# Generated deterministically by seda-macro-lef-normalizer-v1; recipe orfs-asap7-fakeram-m4-v1.
VERSION 5.8 ;
BUSBITCHARS "[]" ;
DIVIDERCHAR "/" ;

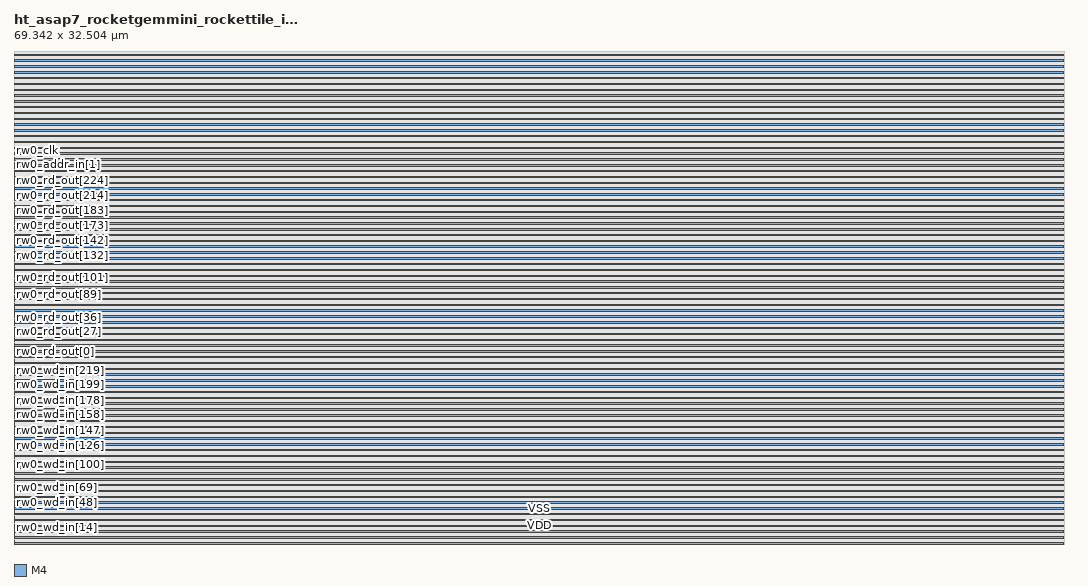
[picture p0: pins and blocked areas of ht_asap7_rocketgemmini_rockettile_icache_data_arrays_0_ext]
MACRO ht_asap7_rocketgemmini_rockettile_icache_data_arrays_0_ext
  FOREIGN ht_asap7_rocketgemmini_rockettile_icache_data_arrays_0_ext 0 0 ;
  CLASS BLOCK ;
  ORIGIN 0 0 ;
  SIZE 69.342 BY 32.504 ;
  SYMMETRY X Y R90 ;
  PIN rw0_wmask_in[0]
    DIRECTION INPUT ;
    USE SIGNAL ;
    SHAPE ABUTMENT ;
    PORT
      LAYER M4 ;
      RECT 0 0.048 0.024 0.072 ;
    END
  END rw0_wmask_in[0]
  PIN rw0_wmask_in[1]
    DIRECTION INPUT ;
    USE SIGNAL ;
    SHAPE ABUTMENT ;
    PORT
      LAYER M4 ;
      RECT 0 0.096 0.024 0.12 ;
    END
  END rw0_wmask_in[1]
  PIN rw0_wmask_in[2]
    DIRECTION INPUT ;
    USE SIGNAL ;
    SHAPE ABUTMENT ;
    PORT
      LAYER M4 ;
      RECT 0 0.144 0.024 0.168 ;
    END
  END rw0_wmask_in[2]
  PIN rw0_wmask_in[3]
    DIRECTION INPUT ;
    USE SIGNAL ;
    SHAPE ABUTMENT ;
    PORT
      LAYER M4 ;
      RECT 0 0.192 0.024 0.216 ;
    END
  END rw0_wmask_in[3]
  PIN rw0_wmask_in[4]
    DIRECTION INPUT ;
    USE SIGNAL ;
    SHAPE ABUTMENT ;
    PORT
      LAYER M4 ;
      RECT 0 0.24 0.024 0.264 ;
    END
  END rw0_wmask_in[4]
  PIN rw0_wmask_in[5]
    DIRECTION INPUT ;
    USE SIGNAL ;
    SHAPE ABUTMENT ;
    PORT
      LAYER M4 ;
      RECT 0 0.288 0.024 0.312 ;
    END
  END rw0_wmask_in[5]
  PIN rw0_wmask_in[6]
    DIRECTION INPUT ;
    USE SIGNAL ;
    SHAPE ABUTMENT ;
    PORT
      LAYER M4 ;
      RECT 0 0.336 0.024 0.36 ;
    END
  END rw0_wmask_in[6]
  PIN rw0_wmask_in[7]
    DIRECTION INPUT ;
    USE SIGNAL ;
    SHAPE ABUTMENT ;
    PORT
      LAYER M4 ;
      RECT 0 0.384 0.024 0.408 ;
    END
  END rw0_wmask_in[7]
  PIN rw0_wd_in[0]
    DIRECTION INPUT ;
    USE SIGNAL ;
    SHAPE ABUTMENT ;
    PORT
      LAYER M4 ;
      RECT 0 0.432 0.024 0.456 ;
    END
  END rw0_wd_in[0]
  PIN rw0_wd_in[1]
    DIRECTION INPUT ;
    USE SIGNAL ;
    SHAPE ABUTMENT ;
    PORT
      LAYER M4 ;
      RECT 0 0.48 0.024 0.504 ;
    END
  END rw0_wd_in[1]
  PIN rw0_wd_in[2]
    DIRECTION INPUT ;
    USE SIGNAL ;
    SHAPE ABUTMENT ;
    PORT
      LAYER M4 ;
      RECT 0 0.528 0.024 0.552 ;
    END
  END rw0_wd_in[2]
  PIN rw0_wd_in[3]
    DIRECTION INPUT ;
    USE SIGNAL ;
    SHAPE ABUTMENT ;
    PORT
      LAYER M4 ;
      RECT 0 0.576 0.024 0.6 ;
    END
  END rw0_wd_in[3]
  PIN rw0_wd_in[4]
    DIRECTION INPUT ;
    USE SIGNAL ;
    SHAPE ABUTMENT ;
    PORT
      LAYER M4 ;
      RECT 0 0.624 0.024 0.648 ;
    END
  END rw0_wd_in[4]
  PIN rw0_wd_in[5]
    DIRECTION INPUT ;
    USE SIGNAL ;
    SHAPE ABUTMENT ;
    PORT
      LAYER M4 ;
      RECT 0 0.672 0.024 0.696 ;
    END
  END rw0_wd_in[5]
  PIN rw0_wd_in[6]
    DIRECTION INPUT ;
    USE SIGNAL ;
    SHAPE ABUTMENT ;
    PORT
      LAYER M4 ;
      RECT 0 0.72 0.024 0.744 ;
    END
  END rw0_wd_in[6]
  PIN rw0_wd_in[7]
    DIRECTION INPUT ;
    USE SIGNAL ;
    SHAPE ABUTMENT ;
    PORT
      LAYER M4 ;
      RECT 0 0.768 0.024 0.792 ;
    END
  END rw0_wd_in[7]
  PIN rw0_wd_in[8]
    DIRECTION INPUT ;
    USE SIGNAL ;
    SHAPE ABUTMENT ;
    PORT
      LAYER M4 ;
      RECT 0 0.816 0.024 0.84 ;
    END
  END rw0_wd_in[8]
  PIN rw0_wd_in[9]
    DIRECTION INPUT ;
    USE SIGNAL ;
    SHAPE ABUTMENT ;
    PORT
      LAYER M4 ;
      RECT 0 0.864 0.024 0.888 ;
    END
  END rw0_wd_in[9]
  PIN rw0_wd_in[10]
    DIRECTION INPUT ;
    USE SIGNAL ;
    SHAPE ABUTMENT ;
    PORT
      LAYER M4 ;
      RECT 0 0.912 0.024 0.936 ;
    END
  END rw0_wd_in[10]
  PIN rw0_wd_in[11]
    DIRECTION INPUT ;
    USE SIGNAL ;
    SHAPE ABUTMENT ;
    PORT
      LAYER M4 ;
      RECT 0 0.96 0.024 0.984 ;
    END
  END rw0_wd_in[11]
  PIN rw0_wd_in[12]
    DIRECTION INPUT ;
    USE SIGNAL ;
    SHAPE ABUTMENT ;
    PORT
      LAYER M4 ;
      RECT 0 1.008 0.024 1.032 ;
    END
  END rw0_wd_in[12]
  PIN rw0_wd_in[13]
    DIRECTION INPUT ;
    USE SIGNAL ;
    SHAPE ABUTMENT ;
    PORT
      LAYER M4 ;
      RECT 0 1.056 0.024 1.08 ;
    END
  END rw0_wd_in[13]
  PIN rw0_wd_in[14]
    DIRECTION INPUT ;
    USE SIGNAL ;
    SHAPE ABUTMENT ;
    PORT
      LAYER M4 ;
      RECT 0 1.104 0.024 1.128 ;
    END
  END rw0_wd_in[14]
  PIN rw0_wd_in[15]
    DIRECTION INPUT ;
    USE SIGNAL ;
    SHAPE ABUTMENT ;
    PORT
      LAYER M4 ;
      RECT 0 1.152 0.024 1.176 ;
    END
  END rw0_wd_in[15]
  PIN rw0_wd_in[16]
    DIRECTION INPUT ;
    USE SIGNAL ;
    SHAPE ABUTMENT ;
    PORT
      LAYER M4 ;
      RECT 0 1.2 0.024 1.224 ;
    END
  END rw0_wd_in[16]
  PIN rw0_wd_in[17]
    DIRECTION INPUT ;
    USE SIGNAL ;
    SHAPE ABUTMENT ;
    PORT
      LAYER M4 ;
      RECT 0 1.248 0.024 1.272 ;
    END
  END rw0_wd_in[17]
  PIN rw0_wd_in[18]
    DIRECTION INPUT ;
    USE SIGNAL ;
    SHAPE ABUTMENT ;
    PORT
      LAYER M4 ;
      RECT 0 1.296 0.024 1.32 ;
    END
  END rw0_wd_in[18]
  PIN rw0_wd_in[19]
    DIRECTION INPUT ;
    USE SIGNAL ;
    SHAPE ABUTMENT ;
    PORT
      LAYER M4 ;
      RECT 0 1.344 0.024 1.368 ;
    END
  END rw0_wd_in[19]
  PIN rw0_wd_in[20]
    DIRECTION INPUT ;
    USE SIGNAL ;
    SHAPE ABUTMENT ;
    PORT
      LAYER M4 ;
      RECT 0 1.392 0.024 1.416 ;
    END
  END rw0_wd_in[20]
  PIN rw0_wd_in[21]
    DIRECTION INPUT ;
    USE SIGNAL ;
    SHAPE ABUTMENT ;
    PORT
      LAYER M4 ;
      RECT 0 1.44 0.024 1.464 ;
    END
  END rw0_wd_in[21]
  PIN rw0_wd_in[22]
    DIRECTION INPUT ;
    USE SIGNAL ;
    SHAPE ABUTMENT ;
    PORT
      LAYER M4 ;
      RECT 0 1.488 0.024 1.512 ;
    END
  END rw0_wd_in[22]
  PIN rw0_wd_in[23]
    DIRECTION INPUT ;
    USE SIGNAL ;
    SHAPE ABUTMENT ;
    PORT
      LAYER M4 ;
      RECT 0 1.536 0.024 1.56 ;
    END
  END rw0_wd_in[23]
  PIN rw0_wd_in[24]
    DIRECTION INPUT ;
    USE SIGNAL ;
    SHAPE ABUTMENT ;
    PORT
      LAYER M4 ;
      RECT 0 1.584 0.024 1.608 ;
    END
  END rw0_wd_in[24]
  PIN rw0_wd_in[25]
    DIRECTION INPUT ;
    USE SIGNAL ;
    SHAPE ABUTMENT ;
    PORT
      LAYER M4 ;
      RECT 0 1.632 0.024 1.656 ;
    END
  END rw0_wd_in[25]
  PIN rw0_wd_in[26]
    DIRECTION INPUT ;
    USE SIGNAL ;
    SHAPE ABUTMENT ;
    PORT
      LAYER M4 ;
      RECT 0 1.68 0.024 1.704 ;
    END
  END rw0_wd_in[26]
  PIN rw0_wd_in[27]
    DIRECTION INPUT ;
    USE SIGNAL ;
    SHAPE ABUTMENT ;
    PORT
      LAYER M4 ;
      RECT 0 1.728 0.024 1.752 ;
    END
  END rw0_wd_in[27]
  PIN rw0_wd_in[28]
    DIRECTION INPUT ;
    USE SIGNAL ;
    SHAPE ABUTMENT ;
    PORT
      LAYER M4 ;
      RECT 0 1.776 0.024 1.8 ;
    END
  END rw0_wd_in[28]
  PIN rw0_wd_in[29]
    DIRECTION INPUT ;
    USE SIGNAL ;
    SHAPE ABUTMENT ;
    PORT
      LAYER M4 ;
      RECT 0 1.824 0.024 1.848 ;
    END
  END rw0_wd_in[29]
  PIN rw0_wd_in[30]
    DIRECTION INPUT ;
    USE SIGNAL ;
    SHAPE ABUTMENT ;
    PORT
      LAYER M4 ;
      RECT 0 1.872 0.024 1.896 ;
    END
  END rw0_wd_in[30]
  PIN rw0_wd_in[31]
    DIRECTION INPUT ;
    USE SIGNAL ;
    SHAPE ABUTMENT ;
    PORT
      LAYER M4 ;
      RECT 0 1.92 0.024 1.944 ;
    END
  END rw0_wd_in[31]
  PIN rw0_wd_in[32]
    DIRECTION INPUT ;
    USE SIGNAL ;
    SHAPE ABUTMENT ;
    PORT
      LAYER M4 ;
      RECT 0 1.968 0.024 1.992 ;
    END
  END rw0_wd_in[32]
  PIN rw0_wd_in[33]
    DIRECTION INPUT ;
    USE SIGNAL ;
    SHAPE ABUTMENT ;
    PORT
      LAYER M4 ;
      RECT 0 2.016 0.024 2.04 ;
    END
  END rw0_wd_in[33]
  PIN rw0_wd_in[34]
    DIRECTION INPUT ;
    USE SIGNAL ;
    SHAPE ABUTMENT ;
    PORT
      LAYER M4 ;
      RECT 0 2.064 0.024 2.088 ;
    END
  END rw0_wd_in[34]
  PIN rw0_wd_in[35]
    DIRECTION INPUT ;
    USE SIGNAL ;
    SHAPE ABUTMENT ;
    PORT
      LAYER M4 ;
      RECT 0 2.112 0.024 2.136 ;
    END
  END rw0_wd_in[35]
  PIN rw0_wd_in[36]
    DIRECTION INPUT ;
    USE SIGNAL ;
    SHAPE ABUTMENT ;
    PORT
      LAYER M4 ;
      RECT 0 2.16 0.024 2.184 ;
    END
  END rw0_wd_in[36]
  PIN rw0_wd_in[37]
    DIRECTION INPUT ;
    USE SIGNAL ;
    SHAPE ABUTMENT ;
    PORT
      LAYER M4 ;
      RECT 0 2.208 0.024 2.232 ;
    END
  END rw0_wd_in[37]
  PIN rw0_wd_in[38]
    DIRECTION INPUT ;
    USE SIGNAL ;
    SHAPE ABUTMENT ;
    PORT
      LAYER M4 ;
      RECT 0 2.256 0.024 2.28 ;
    END
  END rw0_wd_in[38]
  PIN rw0_wd_in[39]
    DIRECTION INPUT ;
    USE SIGNAL ;
    SHAPE ABUTMENT ;
    PORT
      LAYER M4 ;
      RECT 0 2.304 0.024 2.328 ;
    END
  END rw0_wd_in[39]
  PIN rw0_wd_in[40]
    DIRECTION INPUT ;
    USE SIGNAL ;
    SHAPE ABUTMENT ;
    PORT
      LAYER M4 ;
      RECT 0 2.352 0.024 2.376 ;
    END
  END rw0_wd_in[40]
  PIN rw0_wd_in[41]
    DIRECTION INPUT ;
    USE SIGNAL ;
    SHAPE ABUTMENT ;
    PORT
      LAYER M4 ;
      RECT 0 2.4 0.024 2.424 ;
    END
  END rw0_wd_in[41]
  PIN rw0_wd_in[42]
    DIRECTION INPUT ;
    USE SIGNAL ;
    SHAPE ABUTMENT ;
    PORT
      LAYER M4 ;
      RECT 0 2.448 0.024 2.472 ;
    END
  END rw0_wd_in[42]
  PIN rw0_wd_in[43]
    DIRECTION INPUT ;
    USE SIGNAL ;
    SHAPE ABUTMENT ;
    PORT
      LAYER M4 ;
      RECT 0 2.496 0.024 2.52 ;
    END
  END rw0_wd_in[43]
  PIN rw0_wd_in[44]
    DIRECTION INPUT ;
    USE SIGNAL ;
    SHAPE ABUTMENT ;
    PORT
      LAYER M4 ;
      RECT 0 2.544 0.024 2.568 ;
    END
  END rw0_wd_in[44]
  PIN rw0_wd_in[45]
    DIRECTION INPUT ;
    USE SIGNAL ;
    SHAPE ABUTMENT ;
    PORT
      LAYER M4 ;
      RECT 0 2.592 0.024 2.616 ;
    END
  END rw0_wd_in[45]
  PIN rw0_wd_in[46]
    DIRECTION INPUT ;
    USE SIGNAL ;
    SHAPE ABUTMENT ;
    PORT
      LAYER M4 ;
      RECT 0 2.64 0.024 2.664 ;
    END
  END rw0_wd_in[46]
  PIN rw0_wd_in[47]
    DIRECTION INPUT ;
    USE SIGNAL ;
    SHAPE ABUTMENT ;
    PORT
      LAYER M4 ;
      RECT 0 2.688 0.024 2.712 ;
    END
  END rw0_wd_in[47]
  PIN rw0_wd_in[48]
    DIRECTION INPUT ;
    USE SIGNAL ;
    SHAPE ABUTMENT ;
    PORT
      LAYER M4 ;
      RECT 0 2.736 0.024 2.76 ;
    END
  END rw0_wd_in[48]
  PIN rw0_wd_in[49]
    DIRECTION INPUT ;
    USE SIGNAL ;
    SHAPE ABUTMENT ;
    PORT
      LAYER M4 ;
      RECT 0 2.784 0.024 2.808 ;
    END
  END rw0_wd_in[49]
  PIN rw0_wd_in[50]
    DIRECTION INPUT ;
    USE SIGNAL ;
    SHAPE ABUTMENT ;
    PORT
      LAYER M4 ;
      RECT 0 2.832 0.024 2.856 ;
    END
  END rw0_wd_in[50]
  PIN rw0_wd_in[51]
    DIRECTION INPUT ;
    USE SIGNAL ;
    SHAPE ABUTMENT ;
    PORT
      LAYER M4 ;
      RECT 0 2.88 0.024 2.904 ;
    END
  END rw0_wd_in[51]
  PIN rw0_wd_in[52]
    DIRECTION INPUT ;
    USE SIGNAL ;
    SHAPE ABUTMENT ;
    PORT
      LAYER M4 ;
      RECT 0 2.928 0.024 2.952 ;
    END
  END rw0_wd_in[52]
  PIN rw0_wd_in[53]
    DIRECTION INPUT ;
    USE SIGNAL ;
    SHAPE ABUTMENT ;
    PORT
      LAYER M4 ;
      RECT 0 2.976 0.024 3 ;
    END
  END rw0_wd_in[53]
  PIN rw0_wd_in[54]
    DIRECTION INPUT ;
    USE SIGNAL ;
    SHAPE ABUTMENT ;
    PORT
      LAYER M4 ;
      RECT 0 3.024 0.024 3.048 ;
    END
  END rw0_wd_in[54]
  PIN rw0_wd_in[55]
    DIRECTION INPUT ;
    USE SIGNAL ;
    SHAPE ABUTMENT ;
    PORT
      LAYER M4 ;
      RECT 0 3.072 0.024 3.096 ;
    END
  END rw0_wd_in[55]
  PIN rw0_wd_in[56]
    DIRECTION INPUT ;
    USE SIGNAL ;
    SHAPE ABUTMENT ;
    PORT
      LAYER M4 ;
      RECT 0 3.12 0.024 3.144 ;
    END
  END rw0_wd_in[56]
  PIN rw0_wd_in[57]
    DIRECTION INPUT ;
    USE SIGNAL ;
    SHAPE ABUTMENT ;
    PORT
      LAYER M4 ;
      RECT 0 3.168 0.024 3.192 ;
    END
  END rw0_wd_in[57]
  PIN rw0_wd_in[58]
    DIRECTION INPUT ;
    USE SIGNAL ;
    SHAPE ABUTMENT ;
    PORT
      LAYER M4 ;
      RECT 0 3.216 0.024 3.24 ;
    END
  END rw0_wd_in[58]
  PIN rw0_wd_in[59]
    DIRECTION INPUT ;
    USE SIGNAL ;
    SHAPE ABUTMENT ;
    PORT
      LAYER M4 ;
      RECT 0 3.264 0.024 3.288 ;
    END
  END rw0_wd_in[59]
  PIN rw0_wd_in[60]
    DIRECTION INPUT ;
    USE SIGNAL ;
    SHAPE ABUTMENT ;
    PORT
      LAYER M4 ;
      RECT 0 3.312 0.024 3.336 ;
    END
  END rw0_wd_in[60]
  PIN rw0_wd_in[61]
    DIRECTION INPUT ;
    USE SIGNAL ;
    SHAPE ABUTMENT ;
    PORT
      LAYER M4 ;
      RECT 0 3.36 0.024 3.384 ;
    END
  END rw0_wd_in[61]
  PIN rw0_wd_in[62]
    DIRECTION INPUT ;
    USE SIGNAL ;
    SHAPE ABUTMENT ;
    PORT
      LAYER M4 ;
      RECT 0 3.408 0.024 3.432 ;
    END
  END rw0_wd_in[62]
  PIN rw0_wd_in[63]
    DIRECTION INPUT ;
    USE SIGNAL ;
    SHAPE ABUTMENT ;
    PORT
      LAYER M4 ;
      RECT 0 3.456 0.024 3.48 ;
    END
  END rw0_wd_in[63]
  PIN rw0_wd_in[64]
    DIRECTION INPUT ;
    USE SIGNAL ;
    SHAPE ABUTMENT ;
    PORT
      LAYER M4 ;
      RECT 0 3.504 0.024 3.528 ;
    END
  END rw0_wd_in[64]
  PIN rw0_wd_in[65]
    DIRECTION INPUT ;
    USE SIGNAL ;
    SHAPE ABUTMENT ;
    PORT
      LAYER M4 ;
      RECT 0 3.552 0.024 3.576 ;
    END
  END rw0_wd_in[65]
  PIN rw0_wd_in[66]
    DIRECTION INPUT ;
    USE SIGNAL ;
    SHAPE ABUTMENT ;
    PORT
      LAYER M4 ;
      RECT 0 3.6 0.024 3.624 ;
    END
  END rw0_wd_in[66]
  PIN rw0_wd_in[67]
    DIRECTION INPUT ;
    USE SIGNAL ;
    SHAPE ABUTMENT ;
    PORT
      LAYER M4 ;
      RECT 0 3.648 0.024 3.672 ;
    END
  END rw0_wd_in[67]
  PIN rw0_wd_in[68]
    DIRECTION INPUT ;
    USE SIGNAL ;
    SHAPE ABUTMENT ;
    PORT
      LAYER M4 ;
      RECT 0 3.696 0.024 3.72 ;
    END
  END rw0_wd_in[68]
  PIN rw0_wd_in[69]
    DIRECTION INPUT ;
    USE SIGNAL ;
    SHAPE ABUTMENT ;
    PORT
      LAYER M4 ;
      RECT 0 3.744 0.024 3.768 ;
    END
  END rw0_wd_in[69]
  PIN rw0_wd_in[70]
    DIRECTION INPUT ;
    USE SIGNAL ;
    SHAPE ABUTMENT ;
    PORT
      LAYER M4 ;
      RECT 0 3.792 0.024 3.816 ;
    END
  END rw0_wd_in[70]
  PIN rw0_wd_in[71]
    DIRECTION INPUT ;
    USE SIGNAL ;
    SHAPE ABUTMENT ;
    PORT
      LAYER M4 ;
      RECT 0 3.84 0.024 3.864 ;
    END
  END rw0_wd_in[71]
  PIN rw0_wd_in[72]
    DIRECTION INPUT ;
    USE SIGNAL ;
    SHAPE ABUTMENT ;
    PORT
      LAYER M4 ;
      RECT 0 3.888 0.024 3.912 ;
    END
  END rw0_wd_in[72]
  PIN rw0_wd_in[73]
    DIRECTION INPUT ;
    USE SIGNAL ;
    SHAPE ABUTMENT ;
    PORT
      LAYER M4 ;
      RECT 0 3.936 0.024 3.96 ;
    END
  END rw0_wd_in[73]
  PIN rw0_wd_in[74]
    DIRECTION INPUT ;
    USE SIGNAL ;
    SHAPE ABUTMENT ;
    PORT
      LAYER M4 ;
      RECT 0 3.984 0.024 4.008 ;
    END
  END rw0_wd_in[74]
  PIN rw0_wd_in[75]
    DIRECTION INPUT ;
    USE SIGNAL ;
    SHAPE ABUTMENT ;
    PORT
      LAYER M4 ;
      RECT 0 4.032 0.024 4.056 ;
    END
  END rw0_wd_in[75]
  PIN rw0_wd_in[76]
    DIRECTION INPUT ;
    USE SIGNAL ;
    SHAPE ABUTMENT ;
    PORT
      LAYER M4 ;
      RECT 0 4.08 0.024 4.104 ;
    END
  END rw0_wd_in[76]
  PIN rw0_wd_in[77]
    DIRECTION INPUT ;
    USE SIGNAL ;
    SHAPE ABUTMENT ;
    PORT
      LAYER M4 ;
      RECT 0 4.128 0.024 4.152 ;
    END
  END rw0_wd_in[77]
  PIN rw0_wd_in[78]
    DIRECTION INPUT ;
    USE SIGNAL ;
    SHAPE ABUTMENT ;
    PORT
      LAYER M4 ;
      RECT 0 4.176 0.024 4.2 ;
    END
  END rw0_wd_in[78]
  PIN rw0_wd_in[79]
    DIRECTION INPUT ;
    USE SIGNAL ;
    SHAPE ABUTMENT ;
    PORT
      LAYER M4 ;
      RECT 0 4.224 0.024 4.248 ;
    END
  END rw0_wd_in[79]
  PIN rw0_wd_in[80]
    DIRECTION INPUT ;
    USE SIGNAL ;
    SHAPE ABUTMENT ;
    PORT
      LAYER M4 ;
      RECT 0 4.272 0.024 4.296 ;
    END
  END rw0_wd_in[80]
  PIN rw0_wd_in[81]
    DIRECTION INPUT ;
    USE SIGNAL ;
    SHAPE ABUTMENT ;
    PORT
      LAYER M4 ;
      RECT 0 4.32 0.024 4.344 ;
    END
  END rw0_wd_in[81]
  PIN rw0_wd_in[82]
    DIRECTION INPUT ;
    USE SIGNAL ;
    SHAPE ABUTMENT ;
    PORT
      LAYER M4 ;
      RECT 0 4.368 0.024 4.392 ;
    END
  END rw0_wd_in[82]
  PIN rw0_wd_in[83]
    DIRECTION INPUT ;
    USE SIGNAL ;
    SHAPE ABUTMENT ;
    PORT
      LAYER M4 ;
      RECT 0 4.416 0.024 4.44 ;
    END
  END rw0_wd_in[83]
  PIN rw0_wd_in[84]
    DIRECTION INPUT ;
    USE SIGNAL ;
    SHAPE ABUTMENT ;
    PORT
      LAYER M4 ;
      RECT 0 4.464 0.024 4.488 ;
    END
  END rw0_wd_in[84]
  PIN rw0_wd_in[85]
    DIRECTION INPUT ;
    USE SIGNAL ;
    SHAPE ABUTMENT ;
    PORT
      LAYER M4 ;
      RECT 0 4.512 0.024 4.536 ;
    END
  END rw0_wd_in[85]
  PIN rw0_wd_in[86]
    DIRECTION INPUT ;
    USE SIGNAL ;
    SHAPE ABUTMENT ;
    PORT
      LAYER M4 ;
      RECT 0 4.56 0.024 4.584 ;
    END
  END rw0_wd_in[86]
  PIN rw0_wd_in[87]
    DIRECTION INPUT ;
    USE SIGNAL ;
    SHAPE ABUTMENT ;
    PORT
      LAYER M4 ;
      RECT 0 4.608 0.024 4.632 ;
    END
  END rw0_wd_in[87]
  PIN rw0_wd_in[88]
    DIRECTION INPUT ;
    USE SIGNAL ;
    SHAPE ABUTMENT ;
    PORT
      LAYER M4 ;
      RECT 0 4.656 0.024 4.68 ;
    END
  END rw0_wd_in[88]
  PIN rw0_wd_in[89]
    DIRECTION INPUT ;
    USE SIGNAL ;
    SHAPE ABUTMENT ;
    PORT
      LAYER M4 ;
      RECT 0 4.704 0.024 4.728 ;
    END
  END rw0_wd_in[89]
  PIN rw0_wd_in[90]
    DIRECTION INPUT ;
    USE SIGNAL ;
    SHAPE ABUTMENT ;
    PORT
      LAYER M4 ;
      RECT 0 4.752 0.024 4.776 ;
    END
  END rw0_wd_in[90]
  PIN rw0_wd_in[91]
    DIRECTION INPUT ;
    USE SIGNAL ;
    SHAPE ABUTMENT ;
    PORT
      LAYER M4 ;
      RECT 0 4.8 0.024 4.824 ;
    END
  END rw0_wd_in[91]
  PIN rw0_wd_in[92]
    DIRECTION INPUT ;
    USE SIGNAL ;
    SHAPE ABUTMENT ;
    PORT
      LAYER M4 ;
      RECT 0 4.848 0.024 4.872 ;
    END
  END rw0_wd_in[92]
  PIN rw0_wd_in[93]
    DIRECTION INPUT ;
    USE SIGNAL ;
    SHAPE ABUTMENT ;
    PORT
      LAYER M4 ;
      RECT 0 4.896 0.024 4.92 ;
    END
  END rw0_wd_in[93]
  PIN rw0_wd_in[94]
    DIRECTION INPUT ;
    USE SIGNAL ;
    SHAPE ABUTMENT ;
    PORT
      LAYER M4 ;
      RECT 0 4.944 0.024 4.968 ;
    END
  END rw0_wd_in[94]
  PIN rw0_wd_in[95]
    DIRECTION INPUT ;
    USE SIGNAL ;
    SHAPE ABUTMENT ;
    PORT
      LAYER M4 ;
      RECT 0 4.992 0.024 5.016 ;
    END
  END rw0_wd_in[95]
  PIN rw0_wd_in[96]
    DIRECTION INPUT ;
    USE SIGNAL ;
    SHAPE ABUTMENT ;
    PORT
      LAYER M4 ;
      RECT 0 5.04 0.024 5.064 ;
    END
  END rw0_wd_in[96]
  PIN rw0_wd_in[97]
    DIRECTION INPUT ;
    USE SIGNAL ;
    SHAPE ABUTMENT ;
    PORT
      LAYER M4 ;
      RECT 0 5.088 0.024 5.112 ;
    END
  END rw0_wd_in[97]
  PIN rw0_wd_in[98]
    DIRECTION INPUT ;
    USE SIGNAL ;
    SHAPE ABUTMENT ;
    PORT
      LAYER M4 ;
      RECT 0 5.136 0.024 5.16 ;
    END
  END rw0_wd_in[98]
  PIN rw0_wd_in[99]
    DIRECTION INPUT ;
    USE SIGNAL ;
    SHAPE ABUTMENT ;
    PORT
      LAYER M4 ;
      RECT 0 5.184 0.024 5.208 ;
    END
  END rw0_wd_in[99]
  PIN rw0_wd_in[100]
    DIRECTION INPUT ;
    USE SIGNAL ;
    SHAPE ABUTMENT ;
    PORT
      LAYER M4 ;
      RECT 0 5.232 0.024 5.256 ;
    END
  END rw0_wd_in[100]
  PIN rw0_wd_in[101]
    DIRECTION INPUT ;
    USE SIGNAL ;
    SHAPE ABUTMENT ;
    PORT
      LAYER M4 ;
      RECT 0 5.28 0.024 5.304 ;
    END
  END rw0_wd_in[101]
  PIN rw0_wd_in[102]
    DIRECTION INPUT ;
    USE SIGNAL ;
    SHAPE ABUTMENT ;
    PORT
      LAYER M4 ;
      RECT 0 5.328 0.024 5.352 ;
    END
  END rw0_wd_in[102]
  PIN rw0_wd_in[103]
    DIRECTION INPUT ;
    USE SIGNAL ;
    SHAPE ABUTMENT ;
    PORT
      LAYER M4 ;
      RECT 0 5.376 0.024 5.4 ;
    END
  END rw0_wd_in[103]
  PIN rw0_wd_in[104]
    DIRECTION INPUT ;
    USE SIGNAL ;
    SHAPE ABUTMENT ;
    PORT
      LAYER M4 ;
      RECT 0 5.424 0.024 5.448 ;
    END
  END rw0_wd_in[104]
  PIN rw0_wd_in[105]
    DIRECTION INPUT ;
    USE SIGNAL ;
    SHAPE ABUTMENT ;
    PORT
      LAYER M4 ;
      RECT 0 5.472 0.024 5.496 ;
    END
  END rw0_wd_in[105]
  PIN rw0_wd_in[106]
    DIRECTION INPUT ;
    USE SIGNAL ;
    SHAPE ABUTMENT ;
    PORT
      LAYER M4 ;
      RECT 0 5.52 0.024 5.544 ;
    END
  END rw0_wd_in[106]
  PIN rw0_wd_in[107]
    DIRECTION INPUT ;
    USE SIGNAL ;
    SHAPE ABUTMENT ;
    PORT
      LAYER M4 ;
      RECT 0 5.568 0.024 5.592 ;
    END
  END rw0_wd_in[107]
  PIN rw0_wd_in[108]
    DIRECTION INPUT ;
    USE SIGNAL ;
    SHAPE ABUTMENT ;
    PORT
      LAYER M4 ;
      RECT 0 5.616 0.024 5.64 ;
    END
  END rw0_wd_in[108]
  PIN rw0_wd_in[109]
    DIRECTION INPUT ;
    USE SIGNAL ;
    SHAPE ABUTMENT ;
    PORT
      LAYER M4 ;
      RECT 0 5.664 0.024 5.688 ;
    END
  END rw0_wd_in[109]
  PIN rw0_wd_in[110]
    DIRECTION INPUT ;
    USE SIGNAL ;
    SHAPE ABUTMENT ;
    PORT
      LAYER M4 ;
      RECT 0 5.712 0.024 5.736 ;
    END
  END rw0_wd_in[110]
  PIN rw0_wd_in[111]
    DIRECTION INPUT ;
    USE SIGNAL ;
    SHAPE ABUTMENT ;
    PORT
      LAYER M4 ;
      RECT 0 5.76 0.024 5.784 ;
    END
  END rw0_wd_in[111]
  PIN rw0_wd_in[112]
    DIRECTION INPUT ;
    USE SIGNAL ;
    SHAPE ABUTMENT ;
    PORT
      LAYER M4 ;
      RECT 0 5.808 0.024 5.832 ;
    END
  END rw0_wd_in[112]
  PIN rw0_wd_in[113]
    DIRECTION INPUT ;
    USE SIGNAL ;
    SHAPE ABUTMENT ;
    PORT
      LAYER M4 ;
      RECT 0 5.856 0.024 5.88 ;
    END
  END rw0_wd_in[113]
  PIN rw0_wd_in[114]
    DIRECTION INPUT ;
    USE SIGNAL ;
    SHAPE ABUTMENT ;
    PORT
      LAYER M4 ;
      RECT 0 5.904 0.024 5.928 ;
    END
  END rw0_wd_in[114]
  PIN rw0_wd_in[115]
    DIRECTION INPUT ;
    USE SIGNAL ;
    SHAPE ABUTMENT ;
    PORT
      LAYER M4 ;
      RECT 0 5.952 0.024 5.976 ;
    END
  END rw0_wd_in[115]
  PIN rw0_wd_in[116]
    DIRECTION INPUT ;
    USE SIGNAL ;
    SHAPE ABUTMENT ;
    PORT
      LAYER M4 ;
      RECT 0 6 0.024 6.024 ;
    END
  END rw0_wd_in[116]
  PIN rw0_wd_in[117]
    DIRECTION INPUT ;
    USE SIGNAL ;
    SHAPE ABUTMENT ;
    PORT
      LAYER M4 ;
      RECT 0 6.048 0.024 6.072 ;
    END
  END rw0_wd_in[117]
  PIN rw0_wd_in[118]
    DIRECTION INPUT ;
    USE SIGNAL ;
    SHAPE ABUTMENT ;
    PORT
      LAYER M4 ;
      RECT 0 6.096 0.024 6.12 ;
    END
  END rw0_wd_in[118]
  PIN rw0_wd_in[119]
    DIRECTION INPUT ;
    USE SIGNAL ;
    SHAPE ABUTMENT ;
    PORT
      LAYER M4 ;
      RECT 0 6.144 0.024 6.168 ;
    END
  END rw0_wd_in[119]
  PIN rw0_wd_in[120]
    DIRECTION INPUT ;
    USE SIGNAL ;
    SHAPE ABUTMENT ;
    PORT
      LAYER M4 ;
      RECT 0 6.192 0.024 6.216 ;
    END
  END rw0_wd_in[120]
  PIN rw0_wd_in[121]
    DIRECTION INPUT ;
    USE SIGNAL ;
    SHAPE ABUTMENT ;
    PORT
      LAYER M4 ;
      RECT 0 6.24 0.024 6.264 ;
    END
  END rw0_wd_in[121]
  PIN rw0_wd_in[122]
    DIRECTION INPUT ;
    USE SIGNAL ;
    SHAPE ABUTMENT ;
    PORT
      LAYER M4 ;
      RECT 0 6.288 0.024 6.312 ;
    END
  END rw0_wd_in[122]
  PIN rw0_wd_in[123]
    DIRECTION INPUT ;
    USE SIGNAL ;
    SHAPE ABUTMENT ;
    PORT
      LAYER M4 ;
      RECT 0 6.336 0.024 6.36 ;
    END
  END rw0_wd_in[123]
  PIN rw0_wd_in[124]
    DIRECTION INPUT ;
    USE SIGNAL ;
    SHAPE ABUTMENT ;
    PORT
      LAYER M4 ;
      RECT 0 6.384 0.024 6.408 ;
    END
  END rw0_wd_in[124]
  PIN rw0_wd_in[125]
    DIRECTION INPUT ;
    USE SIGNAL ;
    SHAPE ABUTMENT ;
    PORT
      LAYER M4 ;
      RECT 0 6.432 0.024 6.456 ;
    END
  END rw0_wd_in[125]
  PIN rw0_wd_in[126]
    DIRECTION INPUT ;
    USE SIGNAL ;
    SHAPE ABUTMENT ;
    PORT
      LAYER M4 ;
      RECT 0 6.48 0.024 6.504 ;
    END
  END rw0_wd_in[126]
  PIN rw0_wd_in[127]
    DIRECTION INPUT ;
    USE SIGNAL ;
    SHAPE ABUTMENT ;
    PORT
      LAYER M4 ;
      RECT 0 6.528 0.024 6.552 ;
    END
  END rw0_wd_in[127]
  PIN rw0_wd_in[128]
    DIRECTION INPUT ;
    USE SIGNAL ;
    SHAPE ABUTMENT ;
    PORT
      LAYER M4 ;
      RECT 0 6.576 0.024 6.6 ;
    END
  END rw0_wd_in[128]
  PIN rw0_wd_in[129]
    DIRECTION INPUT ;
    USE SIGNAL ;
    SHAPE ABUTMENT ;
    PORT
      LAYER M4 ;
      RECT 0 6.624 0.024 6.648 ;
    END
  END rw0_wd_in[129]
  PIN rw0_wd_in[130]
    DIRECTION INPUT ;
    USE SIGNAL ;
    SHAPE ABUTMENT ;
    PORT
      LAYER M4 ;
      RECT 0 6.672 0.024 6.696 ;
    END
  END rw0_wd_in[130]
  PIN rw0_wd_in[131]
    DIRECTION INPUT ;
    USE SIGNAL ;
    SHAPE ABUTMENT ;
    PORT
      LAYER M4 ;
      RECT 0 6.72 0.024 6.744 ;
    END
  END rw0_wd_in[131]
  PIN rw0_wd_in[132]
    DIRECTION INPUT ;
    USE SIGNAL ;
    SHAPE ABUTMENT ;
    PORT
      LAYER M4 ;
      RECT 0 6.768 0.024 6.792 ;
    END
  END rw0_wd_in[132]
  PIN rw0_wd_in[133]
    DIRECTION INPUT ;
    USE SIGNAL ;
    SHAPE ABUTMENT ;
    PORT
      LAYER M4 ;
      RECT 0 6.816 0.024 6.84 ;
    END
  END rw0_wd_in[133]
  PIN rw0_wd_in[134]
    DIRECTION INPUT ;
    USE SIGNAL ;
    SHAPE ABUTMENT ;
    PORT
      LAYER M4 ;
      RECT 0 6.864 0.024 6.888 ;
    END
  END rw0_wd_in[134]
  PIN rw0_wd_in[135]
    DIRECTION INPUT ;
    USE SIGNAL ;
    SHAPE ABUTMENT ;
    PORT
      LAYER M4 ;
      RECT 0 6.912 0.024 6.936 ;
    END
  END rw0_wd_in[135]
  PIN rw0_wd_in[136]
    DIRECTION INPUT ;
    USE SIGNAL ;
    SHAPE ABUTMENT ;
    PORT
      LAYER M4 ;
      RECT 0 6.96 0.024 6.984 ;
    END
  END rw0_wd_in[136]
  PIN rw0_wd_in[137]
    DIRECTION INPUT ;
    USE SIGNAL ;
    SHAPE ABUTMENT ;
    PORT
      LAYER M4 ;
      RECT 0 7.008 0.024 7.032 ;
    END
  END rw0_wd_in[137]
  PIN rw0_wd_in[138]
    DIRECTION INPUT ;
    USE SIGNAL ;
    SHAPE ABUTMENT ;
    PORT
      LAYER M4 ;
      RECT 0 7.056 0.024 7.08 ;
    END
  END rw0_wd_in[138]
  PIN rw0_wd_in[139]
    DIRECTION INPUT ;
    USE SIGNAL ;
    SHAPE ABUTMENT ;
    PORT
      LAYER M4 ;
      RECT 0 7.104 0.024 7.128 ;
    END
  END rw0_wd_in[139]
  PIN rw0_wd_in[140]
    DIRECTION INPUT ;
    USE SIGNAL ;
    SHAPE ABUTMENT ;
    PORT
      LAYER M4 ;
      RECT 0 7.152 0.024 7.176 ;
    END
  END rw0_wd_in[140]
  PIN rw0_wd_in[141]
    DIRECTION INPUT ;
    USE SIGNAL ;
    SHAPE ABUTMENT ;
    PORT
      LAYER M4 ;
      RECT 0 7.2 0.024 7.224 ;
    END
  END rw0_wd_in[141]
  PIN rw0_wd_in[142]
    DIRECTION INPUT ;
    USE SIGNAL ;
    SHAPE ABUTMENT ;
    PORT
      LAYER M4 ;
      RECT 0 7.248 0.024 7.272 ;
    END
  END rw0_wd_in[142]
  PIN rw0_wd_in[143]
    DIRECTION INPUT ;
    USE SIGNAL ;
    SHAPE ABUTMENT ;
    PORT
      LAYER M4 ;
      RECT 0 7.296 0.024 7.32 ;
    END
  END rw0_wd_in[143]
  PIN rw0_wd_in[144]
    DIRECTION INPUT ;
    USE SIGNAL ;
    SHAPE ABUTMENT ;
    PORT
      LAYER M4 ;
      RECT 0 7.344 0.024 7.368 ;
    END
  END rw0_wd_in[144]
  PIN rw0_wd_in[145]
    DIRECTION INPUT ;
    USE SIGNAL ;
    SHAPE ABUTMENT ;
    PORT
      LAYER M4 ;
      RECT 0 7.392 0.024 7.416 ;
    END
  END rw0_wd_in[145]
  PIN rw0_wd_in[146]
    DIRECTION INPUT ;
    USE SIGNAL ;
    SHAPE ABUTMENT ;
    PORT
      LAYER M4 ;
      RECT 0 7.44 0.024 7.464 ;
    END
  END rw0_wd_in[146]
  PIN rw0_wd_in[147]
    DIRECTION INPUT ;
    USE SIGNAL ;
    SHAPE ABUTMENT ;
    PORT
      LAYER M4 ;
      RECT 0 7.488 0.024 7.512 ;
    END
  END rw0_wd_in[147]
  PIN rw0_wd_in[148]
    DIRECTION INPUT ;
    USE SIGNAL ;
    SHAPE ABUTMENT ;
    PORT
      LAYER M4 ;
      RECT 0 7.536 0.024 7.56 ;
    END
  END rw0_wd_in[148]
  PIN rw0_wd_in[149]
    DIRECTION INPUT ;
    USE SIGNAL ;
    SHAPE ABUTMENT ;
    PORT
      LAYER M4 ;
      RECT 0 7.584 0.024 7.608 ;
    END
  END rw0_wd_in[149]
  PIN rw0_wd_in[150]
    DIRECTION INPUT ;
    USE SIGNAL ;
    SHAPE ABUTMENT ;
    PORT
      LAYER M4 ;
      RECT 0 7.632 0.024 7.656 ;
    END
  END rw0_wd_in[150]
  PIN rw0_wd_in[151]
    DIRECTION INPUT ;
    USE SIGNAL ;
    SHAPE ABUTMENT ;
    PORT
      LAYER M4 ;
      RECT 0 7.68 0.024 7.704 ;
    END
  END rw0_wd_in[151]
  PIN rw0_wd_in[152]
    DIRECTION INPUT ;
    USE SIGNAL ;
    SHAPE ABUTMENT ;
    PORT
      LAYER M4 ;
      RECT 0 7.728 0.024 7.752 ;
    END
  END rw0_wd_in[152]
  PIN rw0_wd_in[153]
    DIRECTION INPUT ;
    USE SIGNAL ;
    SHAPE ABUTMENT ;
    PORT
      LAYER M4 ;
      RECT 0 7.776 0.024 7.8 ;
    END
  END rw0_wd_in[153]
  PIN rw0_wd_in[154]
    DIRECTION INPUT ;
    USE SIGNAL ;
    SHAPE ABUTMENT ;
    PORT
      LAYER M4 ;
      RECT 0 7.824 0.024 7.848 ;
    END
  END rw0_wd_in[154]
  PIN rw0_wd_in[155]
    DIRECTION INPUT ;
    USE SIGNAL ;
    SHAPE ABUTMENT ;
    PORT
      LAYER M4 ;
      RECT 0 7.872 0.024 7.896 ;
    END
  END rw0_wd_in[155]
  PIN rw0_wd_in[156]
    DIRECTION INPUT ;
    USE SIGNAL ;
    SHAPE ABUTMENT ;
    PORT
      LAYER M4 ;
      RECT 0 7.92 0.024 7.944 ;
    END
  END rw0_wd_in[156]
  PIN rw0_wd_in[157]
    DIRECTION INPUT ;
    USE SIGNAL ;
    SHAPE ABUTMENT ;
    PORT
      LAYER M4 ;
      RECT 0 7.968 0.024 7.992 ;
    END
  END rw0_wd_in[157]
  PIN rw0_wd_in[158]
    DIRECTION INPUT ;
    USE SIGNAL ;
    SHAPE ABUTMENT ;
    PORT
      LAYER M4 ;
      RECT 0 8.016 0.024 8.04 ;
    END
  END rw0_wd_in[158]
  PIN rw0_wd_in[159]
    DIRECTION INPUT ;
    USE SIGNAL ;
    SHAPE ABUTMENT ;
    PORT
      LAYER M4 ;
      RECT 0 8.064 0.024 8.088 ;
    END
  END rw0_wd_in[159]
  PIN rw0_wd_in[160]
    DIRECTION INPUT ;
    USE SIGNAL ;
    SHAPE ABUTMENT ;
    PORT
      LAYER M4 ;
      RECT 0 8.112 0.024 8.136 ;
    END
  END rw0_wd_in[160]
  PIN rw0_wd_in[161]
    DIRECTION INPUT ;
    USE SIGNAL ;
    SHAPE ABUTMENT ;
    PORT
      LAYER M4 ;
      RECT 0 8.16 0.024 8.184 ;
    END
  END rw0_wd_in[161]
  PIN rw0_wd_in[162]
    DIRECTION INPUT ;
    USE SIGNAL ;
    SHAPE ABUTMENT ;
    PORT
      LAYER M4 ;
      RECT 0 8.208 0.024 8.232 ;
    END
  END rw0_wd_in[162]
  PIN rw0_wd_in[163]
    DIRECTION INPUT ;
    USE SIGNAL ;
    SHAPE ABUTMENT ;
    PORT
      LAYER M4 ;
      RECT 0 8.256 0.024 8.28 ;
    END
  END rw0_wd_in[163]
  PIN rw0_wd_in[164]
    DIRECTION INPUT ;
    USE SIGNAL ;
    SHAPE ABUTMENT ;
    PORT
      LAYER M4 ;
      RECT 0 8.304 0.024 8.328 ;
    END
  END rw0_wd_in[164]
  PIN rw0_wd_in[165]
    DIRECTION INPUT ;
    USE SIGNAL ;
    SHAPE ABUTMENT ;
    PORT
      LAYER M4 ;
      RECT 0 8.352 0.024 8.376 ;
    END
  END rw0_wd_in[165]
  PIN rw0_wd_in[166]
    DIRECTION INPUT ;
    USE SIGNAL ;
    SHAPE ABUTMENT ;
    PORT
      LAYER M4 ;
      RECT 0 8.4 0.024 8.424 ;
    END
  END rw0_wd_in[166]
  PIN rw0_wd_in[167]
    DIRECTION INPUT ;
    USE SIGNAL ;
    SHAPE ABUTMENT ;
    PORT
      LAYER M4 ;
      RECT 0 8.448 0.024 8.472 ;
    END
  END rw0_wd_in[167]
  PIN rw0_wd_in[168]
    DIRECTION INPUT ;
    USE SIGNAL ;
    SHAPE ABUTMENT ;
    PORT
      LAYER M4 ;
      RECT 0 8.496 0.024 8.52 ;
    END
  END rw0_wd_in[168]
  PIN rw0_wd_in[169]
    DIRECTION INPUT ;
    USE SIGNAL ;
    SHAPE ABUTMENT ;
    PORT
      LAYER M4 ;
      RECT 0 8.544 0.024 8.568 ;
    END
  END rw0_wd_in[169]
  PIN rw0_wd_in[170]
    DIRECTION INPUT ;
    USE SIGNAL ;
    SHAPE ABUTMENT ;
    PORT
      LAYER M4 ;
      RECT 0 8.592 0.024 8.616 ;
    END
  END rw0_wd_in[170]
  PIN rw0_wd_in[171]
    DIRECTION INPUT ;
    USE SIGNAL ;
    SHAPE ABUTMENT ;
    PORT
      LAYER M4 ;
      RECT 0 8.64 0.024 8.664 ;
    END
  END rw0_wd_in[171]
  PIN rw0_wd_in[172]
    DIRECTION INPUT ;
    USE SIGNAL ;
    SHAPE ABUTMENT ;
    PORT
      LAYER M4 ;
      RECT 0 8.688 0.024 8.712 ;
    END
  END rw0_wd_in[172]
  PIN rw0_wd_in[173]
    DIRECTION INPUT ;
    USE SIGNAL ;
    SHAPE ABUTMENT ;
    PORT
      LAYER M4 ;
      RECT 0 8.736 0.024 8.76 ;
    END
  END rw0_wd_in[173]
  PIN rw0_wd_in[174]
    DIRECTION INPUT ;
    USE SIGNAL ;
    SHAPE ABUTMENT ;
    PORT
      LAYER M4 ;
      RECT 0 8.784 0.024 8.808 ;
    END
  END rw0_wd_in[174]
  PIN rw0_wd_in[175]
    DIRECTION INPUT ;
    USE SIGNAL ;
    SHAPE ABUTMENT ;
    PORT
      LAYER M4 ;
      RECT 0 8.832 0.024 8.856 ;
    END
  END rw0_wd_in[175]
  PIN rw0_wd_in[176]
    DIRECTION INPUT ;
    USE SIGNAL ;
    SHAPE ABUTMENT ;
    PORT
      LAYER M4 ;
      RECT 0 8.88 0.024 8.904 ;
    END
  END rw0_wd_in[176]
  PIN rw0_wd_in[177]
    DIRECTION INPUT ;
    USE SIGNAL ;
    SHAPE ABUTMENT ;
    PORT
      LAYER M4 ;
      RECT 0 8.928 0.024 8.952 ;
    END
  END rw0_wd_in[177]
  PIN rw0_wd_in[178]
    DIRECTION INPUT ;
    USE SIGNAL ;
    SHAPE ABUTMENT ;
    PORT
      LAYER M4 ;
      RECT 0 8.976 0.024 9 ;
    END
  END rw0_wd_in[178]
  PIN rw0_wd_in[179]
    DIRECTION INPUT ;
    USE SIGNAL ;
    SHAPE ABUTMENT ;
    PORT
      LAYER M4 ;
      RECT 0 9.024 0.024 9.048 ;
    END
  END rw0_wd_in[179]
  PIN rw0_wd_in[180]
    DIRECTION INPUT ;
    USE SIGNAL ;
    SHAPE ABUTMENT ;
    PORT
      LAYER M4 ;
      RECT 0 9.072 0.024 9.096 ;
    END
  END rw0_wd_in[180]
  PIN rw0_wd_in[181]
    DIRECTION INPUT ;
    USE SIGNAL ;
    SHAPE ABUTMENT ;
    PORT
      LAYER M4 ;
      RECT 0 9.12 0.024 9.144 ;
    END
  END rw0_wd_in[181]
  PIN rw0_wd_in[182]
    DIRECTION INPUT ;
    USE SIGNAL ;
    SHAPE ABUTMENT ;
    PORT
      LAYER M4 ;
      RECT 0 9.168 0.024 9.192 ;
    END
  END rw0_wd_in[182]
  PIN rw0_wd_in[183]
    DIRECTION INPUT ;
    USE SIGNAL ;
    SHAPE ABUTMENT ;
    PORT
      LAYER M4 ;
      RECT 0 9.216 0.024 9.24 ;
    END
  END rw0_wd_in[183]
  PIN rw0_wd_in[184]
    DIRECTION INPUT ;
    USE SIGNAL ;
    SHAPE ABUTMENT ;
    PORT
      LAYER M4 ;
      RECT 0 9.264 0.024 9.288 ;
    END
  END rw0_wd_in[184]
  PIN rw0_wd_in[185]
    DIRECTION INPUT ;
    USE SIGNAL ;
    SHAPE ABUTMENT ;
    PORT
      LAYER M4 ;
      RECT 0 9.312 0.024 9.336 ;
    END
  END rw0_wd_in[185]
  PIN rw0_wd_in[186]
    DIRECTION INPUT ;
    USE SIGNAL ;
    SHAPE ABUTMENT ;
    PORT
      LAYER M4 ;
      RECT 0 9.36 0.024 9.384 ;
    END
  END rw0_wd_in[186]
  PIN rw0_wd_in[187]
    DIRECTION INPUT ;
    USE SIGNAL ;
    SHAPE ABUTMENT ;
    PORT
      LAYER M4 ;
      RECT 0 9.408 0.024 9.432 ;
    END
  END rw0_wd_in[187]
  PIN rw0_wd_in[188]
    DIRECTION INPUT ;
    USE SIGNAL ;
    SHAPE ABUTMENT ;
    PORT
      LAYER M4 ;
      RECT 0 9.456 0.024 9.48 ;
    END
  END rw0_wd_in[188]
  PIN rw0_wd_in[189]
    DIRECTION INPUT ;
    USE SIGNAL ;
    SHAPE ABUTMENT ;
    PORT
      LAYER M4 ;
      RECT 0 9.504 0.024 9.528 ;
    END
  END rw0_wd_in[189]
  PIN rw0_wd_in[190]
    DIRECTION INPUT ;
    USE SIGNAL ;
    SHAPE ABUTMENT ;
    PORT
      LAYER M4 ;
      RECT 0 9.552 0.024 9.576 ;
    END
  END rw0_wd_in[190]
  PIN rw0_wd_in[191]
    DIRECTION INPUT ;
    USE SIGNAL ;
    SHAPE ABUTMENT ;
    PORT
      LAYER M4 ;
      RECT 0 9.6 0.024 9.624 ;
    END
  END rw0_wd_in[191]
  PIN rw0_wd_in[192]
    DIRECTION INPUT ;
    USE SIGNAL ;
    SHAPE ABUTMENT ;
    PORT
      LAYER M4 ;
      RECT 0 9.648 0.024 9.672 ;
    END
  END rw0_wd_in[192]
  PIN rw0_wd_in[193]
    DIRECTION INPUT ;
    USE SIGNAL ;
    SHAPE ABUTMENT ;
    PORT
      LAYER M4 ;
      RECT 0 9.696 0.024 9.72 ;
    END
  END rw0_wd_in[193]
  PIN rw0_wd_in[194]
    DIRECTION INPUT ;
    USE SIGNAL ;
    SHAPE ABUTMENT ;
    PORT
      LAYER M4 ;
      RECT 0 9.744 0.024 9.768 ;
    END
  END rw0_wd_in[194]
  PIN rw0_wd_in[195]
    DIRECTION INPUT ;
    USE SIGNAL ;
    SHAPE ABUTMENT ;
    PORT
      LAYER M4 ;
      RECT 0 9.792 0.024 9.816 ;
    END
  END rw0_wd_in[195]
  PIN rw0_wd_in[196]
    DIRECTION INPUT ;
    USE SIGNAL ;
    SHAPE ABUTMENT ;
    PORT
      LAYER M4 ;
      RECT 0 9.84 0.024 9.864 ;
    END
  END rw0_wd_in[196]
  PIN rw0_wd_in[197]
    DIRECTION INPUT ;
    USE SIGNAL ;
    SHAPE ABUTMENT ;
    PORT
      LAYER M4 ;
      RECT 0 9.888 0.024 9.912 ;
    END
  END rw0_wd_in[197]
  PIN rw0_wd_in[198]
    DIRECTION INPUT ;
    USE SIGNAL ;
    SHAPE ABUTMENT ;
    PORT
      LAYER M4 ;
      RECT 0 9.936 0.024 9.96 ;
    END
  END rw0_wd_in[198]
  PIN rw0_wd_in[199]
    DIRECTION INPUT ;
    USE SIGNAL ;
    SHAPE ABUTMENT ;
    PORT
      LAYER M4 ;
      RECT 0 9.984 0.024 10.008 ;
    END
  END rw0_wd_in[199]
  PIN rw0_wd_in[200]
    DIRECTION INPUT ;
    USE SIGNAL ;
    SHAPE ABUTMENT ;
    PORT
      LAYER M4 ;
      RECT 0 10.032 0.024 10.056 ;
    END
  END rw0_wd_in[200]
  PIN rw0_wd_in[201]
    DIRECTION INPUT ;
    USE SIGNAL ;
    SHAPE ABUTMENT ;
    PORT
      LAYER M4 ;
      RECT 0 10.08 0.024 10.104 ;
    END
  END rw0_wd_in[201]
  PIN rw0_wd_in[202]
    DIRECTION INPUT ;
    USE SIGNAL ;
    SHAPE ABUTMENT ;
    PORT
      LAYER M4 ;
      RECT 0 10.128 0.024 10.152 ;
    END
  END rw0_wd_in[202]
  PIN rw0_wd_in[203]
    DIRECTION INPUT ;
    USE SIGNAL ;
    SHAPE ABUTMENT ;
    PORT
      LAYER M4 ;
      RECT 0 10.176 0.024 10.2 ;
    END
  END rw0_wd_in[203]
  PIN rw0_wd_in[204]
    DIRECTION INPUT ;
    USE SIGNAL ;
    SHAPE ABUTMENT ;
    PORT
      LAYER M4 ;
      RECT 0 10.224 0.024 10.248 ;
    END
  END rw0_wd_in[204]
  PIN rw0_wd_in[205]
    DIRECTION INPUT ;
    USE SIGNAL ;
    SHAPE ABUTMENT ;
    PORT
      LAYER M4 ;
      RECT 0 10.272 0.024 10.296 ;
    END
  END rw0_wd_in[205]
  PIN rw0_wd_in[206]
    DIRECTION INPUT ;
    USE SIGNAL ;
    SHAPE ABUTMENT ;
    PORT
      LAYER M4 ;
      RECT 0 10.32 0.024 10.344 ;
    END
  END rw0_wd_in[206]
  PIN rw0_wd_in[207]
    DIRECTION INPUT ;
    USE SIGNAL ;
    SHAPE ABUTMENT ;
    PORT
      LAYER M4 ;
      RECT 0 10.368 0.024 10.392 ;
    END
  END rw0_wd_in[207]
  PIN rw0_wd_in[208]
    DIRECTION INPUT ;
    USE SIGNAL ;
    SHAPE ABUTMENT ;
    PORT
      LAYER M4 ;
      RECT 0 10.416 0.024 10.44 ;
    END
  END rw0_wd_in[208]
  PIN rw0_wd_in[209]
    DIRECTION INPUT ;
    USE SIGNAL ;
    SHAPE ABUTMENT ;
    PORT
      LAYER M4 ;
      RECT 0 10.464 0.024 10.488 ;
    END
  END rw0_wd_in[209]
  PIN rw0_wd_in[210]
    DIRECTION INPUT ;
    USE SIGNAL ;
    SHAPE ABUTMENT ;
    PORT
      LAYER M4 ;
      RECT 0 10.512 0.024 10.536 ;
    END
  END rw0_wd_in[210]
  PIN rw0_wd_in[211]
    DIRECTION INPUT ;
    USE SIGNAL ;
    SHAPE ABUTMENT ;
    PORT
      LAYER M4 ;
      RECT 0 10.56 0.024 10.584 ;
    END
  END rw0_wd_in[211]
  PIN rw0_wd_in[212]
    DIRECTION INPUT ;
    USE SIGNAL ;
    SHAPE ABUTMENT ;
    PORT
      LAYER M4 ;
      RECT 0 10.608 0.024 10.632 ;
    END
  END rw0_wd_in[212]
  PIN rw0_wd_in[213]
    DIRECTION INPUT ;
    USE SIGNAL ;
    SHAPE ABUTMENT ;
    PORT
      LAYER M4 ;
      RECT 0 10.656 0.024 10.68 ;
    END
  END rw0_wd_in[213]
  PIN rw0_wd_in[214]
    DIRECTION INPUT ;
    USE SIGNAL ;
    SHAPE ABUTMENT ;
    PORT
      LAYER M4 ;
      RECT 0 10.704 0.024 10.728 ;
    END
  END rw0_wd_in[214]
  PIN rw0_wd_in[215]
    DIRECTION INPUT ;
    USE SIGNAL ;
    SHAPE ABUTMENT ;
    PORT
      LAYER M4 ;
      RECT 0 10.752 0.024 10.776 ;
    END
  END rw0_wd_in[215]
  PIN rw0_wd_in[216]
    DIRECTION INPUT ;
    USE SIGNAL ;
    SHAPE ABUTMENT ;
    PORT
      LAYER M4 ;
      RECT 0 10.8 0.024 10.824 ;
    END
  END rw0_wd_in[216]
  PIN rw0_wd_in[217]
    DIRECTION INPUT ;
    USE SIGNAL ;
    SHAPE ABUTMENT ;
    PORT
      LAYER M4 ;
      RECT 0 10.848 0.024 10.872 ;
    END
  END rw0_wd_in[217]
  PIN rw0_wd_in[218]
    DIRECTION INPUT ;
    USE SIGNAL ;
    SHAPE ABUTMENT ;
    PORT
      LAYER M4 ;
      RECT 0 10.896 0.024 10.92 ;
    END
  END rw0_wd_in[218]
  PIN rw0_wd_in[219]
    DIRECTION INPUT ;
    USE SIGNAL ;
    SHAPE ABUTMENT ;
    PORT
      LAYER M4 ;
      RECT 0 10.944 0.024 10.968 ;
    END
  END rw0_wd_in[219]
  PIN rw0_wd_in[220]
    DIRECTION INPUT ;
    USE SIGNAL ;
    SHAPE ABUTMENT ;
    PORT
      LAYER M4 ;
      RECT 0 10.992 0.024 11.016 ;
    END
  END rw0_wd_in[220]
  PIN rw0_wd_in[221]
    DIRECTION INPUT ;
    USE SIGNAL ;
    SHAPE ABUTMENT ;
    PORT
      LAYER M4 ;
      RECT 0 11.04 0.024 11.064 ;
    END
  END rw0_wd_in[221]
  PIN rw0_wd_in[222]
    DIRECTION INPUT ;
    USE SIGNAL ;
    SHAPE ABUTMENT ;
    PORT
      LAYER M4 ;
      RECT 0 11.088 0.024 11.112 ;
    END
  END rw0_wd_in[222]
  PIN rw0_wd_in[223]
    DIRECTION INPUT ;
    USE SIGNAL ;
    SHAPE ABUTMENT ;
    PORT
      LAYER M4 ;
      RECT 0 11.136 0.024 11.16 ;
    END
  END rw0_wd_in[223]
  PIN rw0_wd_in[224]
    DIRECTION INPUT ;
    USE SIGNAL ;
    SHAPE ABUTMENT ;
    PORT
      LAYER M4 ;
      RECT 0 11.184 0.024 11.208 ;
    END
  END rw0_wd_in[224]
  PIN rw0_wd_in[225]
    DIRECTION INPUT ;
    USE SIGNAL ;
    SHAPE ABUTMENT ;
    PORT
      LAYER M4 ;
      RECT 0 11.232 0.024 11.256 ;
    END
  END rw0_wd_in[225]
  PIN rw0_wd_in[226]
    DIRECTION INPUT ;
    USE SIGNAL ;
    SHAPE ABUTMENT ;
    PORT
      LAYER M4 ;
      RECT 0 11.28 0.024 11.304 ;
    END
  END rw0_wd_in[226]
  PIN rw0_wd_in[227]
    DIRECTION INPUT ;
    USE SIGNAL ;
    SHAPE ABUTMENT ;
    PORT
      LAYER M4 ;
      RECT 0 11.328 0.024 11.352 ;
    END
  END rw0_wd_in[227]
  PIN rw0_wd_in[228]
    DIRECTION INPUT ;
    USE SIGNAL ;
    SHAPE ABUTMENT ;
    PORT
      LAYER M4 ;
      RECT 0 11.376 0.024 11.4 ;
    END
  END rw0_wd_in[228]
  PIN rw0_wd_in[229]
    DIRECTION INPUT ;
    USE SIGNAL ;
    SHAPE ABUTMENT ;
    PORT
      LAYER M4 ;
      RECT 0 11.424 0.024 11.448 ;
    END
  END rw0_wd_in[229]
  PIN rw0_wd_in[230]
    DIRECTION INPUT ;
    USE SIGNAL ;
    SHAPE ABUTMENT ;
    PORT
      LAYER M4 ;
      RECT 0 11.472 0.024 11.496 ;
    END
  END rw0_wd_in[230]
  PIN rw0_wd_in[231]
    DIRECTION INPUT ;
    USE SIGNAL ;
    SHAPE ABUTMENT ;
    PORT
      LAYER M4 ;
      RECT 0 11.52 0.024 11.544 ;
    END
  END rw0_wd_in[231]
  PIN rw0_wd_in[232]
    DIRECTION INPUT ;
    USE SIGNAL ;
    SHAPE ABUTMENT ;
    PORT
      LAYER M4 ;
      RECT 0 11.568 0.024 11.592 ;
    END
  END rw0_wd_in[232]
  PIN rw0_wd_in[233]
    DIRECTION INPUT ;
    USE SIGNAL ;
    SHAPE ABUTMENT ;
    PORT
      LAYER M4 ;
      RECT 0 11.616 0.024 11.64 ;
    END
  END rw0_wd_in[233]
  PIN rw0_wd_in[234]
    DIRECTION INPUT ;
    USE SIGNAL ;
    SHAPE ABUTMENT ;
    PORT
      LAYER M4 ;
      RECT 0 11.664 0.024 11.688 ;
    END
  END rw0_wd_in[234]
  PIN rw0_wd_in[235]
    DIRECTION INPUT ;
    USE SIGNAL ;
    SHAPE ABUTMENT ;
    PORT
      LAYER M4 ;
      RECT 0 11.712 0.024 11.736 ;
    END
  END rw0_wd_in[235]
  PIN rw0_wd_in[236]
    DIRECTION INPUT ;
    USE SIGNAL ;
    SHAPE ABUTMENT ;
    PORT
      LAYER M4 ;
      RECT 0 11.76 0.024 11.784 ;
    END
  END rw0_wd_in[236]
  PIN rw0_wd_in[237]
    DIRECTION INPUT ;
    USE SIGNAL ;
    SHAPE ABUTMENT ;
    PORT
      LAYER M4 ;
      RECT 0 11.808 0.024 11.832 ;
    END
  END rw0_wd_in[237]
  PIN rw0_wd_in[238]
    DIRECTION INPUT ;
    USE SIGNAL ;
    SHAPE ABUTMENT ;
    PORT
      LAYER M4 ;
      RECT 0 11.856 0.024 11.88 ;
    END
  END rw0_wd_in[238]
  PIN rw0_wd_in[239]
    DIRECTION INPUT ;
    USE SIGNAL ;
    SHAPE ABUTMENT ;
    PORT
      LAYER M4 ;
      RECT 0 11.904 0.024 11.928 ;
    END
  END rw0_wd_in[239]
  PIN rw0_wd_in[240]
    DIRECTION INPUT ;
    USE SIGNAL ;
    SHAPE ABUTMENT ;
    PORT
      LAYER M4 ;
      RECT 0 11.952 0.024 11.976 ;
    END
  END rw0_wd_in[240]
  PIN rw0_wd_in[241]
    DIRECTION INPUT ;
    USE SIGNAL ;
    SHAPE ABUTMENT ;
    PORT
      LAYER M4 ;
      RECT 0 12 0.024 12.024 ;
    END
  END rw0_wd_in[241]
  PIN rw0_wd_in[242]
    DIRECTION INPUT ;
    USE SIGNAL ;
    SHAPE ABUTMENT ;
    PORT
      LAYER M4 ;
      RECT 0 12.048 0.024 12.072 ;
    END
  END rw0_wd_in[242]
  PIN rw0_wd_in[243]
    DIRECTION INPUT ;
    USE SIGNAL ;
    SHAPE ABUTMENT ;
    PORT
      LAYER M4 ;
      RECT 0 12.096 0.024 12.12 ;
    END
  END rw0_wd_in[243]
  PIN rw0_wd_in[244]
    DIRECTION INPUT ;
    USE SIGNAL ;
    SHAPE ABUTMENT ;
    PORT
      LAYER M4 ;
      RECT 0 12.144 0.024 12.168 ;
    END
  END rw0_wd_in[244]
  PIN rw0_wd_in[245]
    DIRECTION INPUT ;
    USE SIGNAL ;
    SHAPE ABUTMENT ;
    PORT
      LAYER M4 ;
      RECT 0 12.192 0.024 12.216 ;
    END
  END rw0_wd_in[245]
  PIN rw0_wd_in[246]
    DIRECTION INPUT ;
    USE SIGNAL ;
    SHAPE ABUTMENT ;
    PORT
      LAYER M4 ;
      RECT 0 12.24 0.024 12.264 ;
    END
  END rw0_wd_in[246]
  PIN rw0_wd_in[247]
    DIRECTION INPUT ;
    USE SIGNAL ;
    SHAPE ABUTMENT ;
    PORT
      LAYER M4 ;
      RECT 0 12.288 0.024 12.312 ;
    END
  END rw0_wd_in[247]
  PIN rw0_wd_in[248]
    DIRECTION INPUT ;
    USE SIGNAL ;
    SHAPE ABUTMENT ;
    PORT
      LAYER M4 ;
      RECT 0 12.336 0.024 12.36 ;
    END
  END rw0_wd_in[248]
  PIN rw0_wd_in[249]
    DIRECTION INPUT ;
    USE SIGNAL ;
    SHAPE ABUTMENT ;
    PORT
      LAYER M4 ;
      RECT 0 12.384 0.024 12.408 ;
    END
  END rw0_wd_in[249]
  PIN rw0_wd_in[250]
    DIRECTION INPUT ;
    USE SIGNAL ;
    SHAPE ABUTMENT ;
    PORT
      LAYER M4 ;
      RECT 0 12.432 0.024 12.456 ;
    END
  END rw0_wd_in[250]
  PIN rw0_wd_in[251]
    DIRECTION INPUT ;
    USE SIGNAL ;
    SHAPE ABUTMENT ;
    PORT
      LAYER M4 ;
      RECT 0 12.48 0.024 12.504 ;
    END
  END rw0_wd_in[251]
  PIN rw0_wd_in[252]
    DIRECTION INPUT ;
    USE SIGNAL ;
    SHAPE ABUTMENT ;
    PORT
      LAYER M4 ;
      RECT 0 12.528 0.024 12.552 ;
    END
  END rw0_wd_in[252]
  PIN rw0_wd_in[253]
    DIRECTION INPUT ;
    USE SIGNAL ;
    SHAPE ABUTMENT ;
    PORT
      LAYER M4 ;
      RECT 0 12.576 0.024 12.6 ;
    END
  END rw0_wd_in[253]
  PIN rw0_wd_in[254]
    DIRECTION INPUT ;
    USE SIGNAL ;
    SHAPE ABUTMENT ;
    PORT
      LAYER M4 ;
      RECT 0 12.624 0.024 12.648 ;
    END
  END rw0_wd_in[254]
  PIN rw0_wd_in[255]
    DIRECTION INPUT ;
    USE SIGNAL ;
    SHAPE ABUTMENT ;
    PORT
      LAYER M4 ;
      RECT 0 12.672 0.024 12.696 ;
    END
  END rw0_wd_in[255]
  PIN rw0_rd_out[0]
    DIRECTION OUTPUT ;
    USE SIGNAL ;
    SHAPE ABUTMENT ;
    PORT
      LAYER M4 ;
      RECT 0 12.72 0.024 12.744 ;
    END
  END rw0_rd_out[0]
  PIN rw0_rd_out[1]
    DIRECTION OUTPUT ;
    USE SIGNAL ;
    SHAPE ABUTMENT ;
    PORT
      LAYER M4 ;
      RECT 0 12.768 0.024 12.792 ;
    END
  END rw0_rd_out[1]
  PIN rw0_rd_out[2]
    DIRECTION OUTPUT ;
    USE SIGNAL ;
    SHAPE ABUTMENT ;
    PORT
      LAYER M4 ;
      RECT 0 12.816 0.024 12.84 ;
    END
  END rw0_rd_out[2]
  PIN rw0_rd_out[3]
    DIRECTION OUTPUT ;
    USE SIGNAL ;
    SHAPE ABUTMENT ;
    PORT
      LAYER M4 ;
      RECT 0 12.864 0.024 12.888 ;
    END
  END rw0_rd_out[3]
  PIN rw0_rd_out[4]
    DIRECTION OUTPUT ;
    USE SIGNAL ;
    SHAPE ABUTMENT ;
    PORT
      LAYER M4 ;
      RECT 0 12.912 0.024 12.936 ;
    END
  END rw0_rd_out[4]
  PIN rw0_rd_out[5]
    DIRECTION OUTPUT ;
    USE SIGNAL ;
    SHAPE ABUTMENT ;
    PORT
      LAYER M4 ;
      RECT 0 12.96 0.024 12.984 ;
    END
  END rw0_rd_out[5]
  PIN rw0_rd_out[6]
    DIRECTION OUTPUT ;
    USE SIGNAL ;
    SHAPE ABUTMENT ;
    PORT
      LAYER M4 ;
      RECT 0 13.008 0.024 13.032 ;
    END
  END rw0_rd_out[6]
  PIN rw0_rd_out[7]
    DIRECTION OUTPUT ;
    USE SIGNAL ;
    SHAPE ABUTMENT ;
    PORT
      LAYER M4 ;
      RECT 0 13.056 0.024 13.08 ;
    END
  END rw0_rd_out[7]
  PIN rw0_rd_out[8]
    DIRECTION OUTPUT ;
    USE SIGNAL ;
    SHAPE ABUTMENT ;
    PORT
      LAYER M4 ;
      RECT 0 13.104 0.024 13.128 ;
    END
  END rw0_rd_out[8]
  PIN rw0_rd_out[9]
    DIRECTION OUTPUT ;
    USE SIGNAL ;
    SHAPE ABUTMENT ;
    PORT
      LAYER M4 ;
      RECT 0 13.152 0.024 13.176 ;
    END
  END rw0_rd_out[9]
  PIN rw0_rd_out[10]
    DIRECTION OUTPUT ;
    USE SIGNAL ;
    SHAPE ABUTMENT ;
    PORT
      LAYER M4 ;
      RECT 0 13.2 0.024 13.224 ;
    END
  END rw0_rd_out[10]
  PIN rw0_rd_out[11]
    DIRECTION OUTPUT ;
    USE SIGNAL ;
    SHAPE ABUTMENT ;
    PORT
      LAYER M4 ;
      RECT 0 13.248 0.024 13.272 ;
    END
  END rw0_rd_out[11]
  PIN rw0_rd_out[12]
    DIRECTION OUTPUT ;
    USE SIGNAL ;
    SHAPE ABUTMENT ;
    PORT
      LAYER M4 ;
      RECT 0 13.296 0.024 13.32 ;
    END
  END rw0_rd_out[12]
  PIN rw0_rd_out[13]
    DIRECTION OUTPUT ;
    USE SIGNAL ;
    SHAPE ABUTMENT ;
    PORT
      LAYER M4 ;
      RECT 0 13.344 0.024 13.368 ;
    END
  END rw0_rd_out[13]
  PIN rw0_rd_out[14]
    DIRECTION OUTPUT ;
    USE SIGNAL ;
    SHAPE ABUTMENT ;
    PORT
      LAYER M4 ;
      RECT 0 13.392 0.024 13.416 ;
    END
  END rw0_rd_out[14]
  PIN rw0_rd_out[15]
    DIRECTION OUTPUT ;
    USE SIGNAL ;
    SHAPE ABUTMENT ;
    PORT
      LAYER M4 ;
      RECT 0 13.44 0.024 13.464 ;
    END
  END rw0_rd_out[15]
  PIN rw0_rd_out[16]
    DIRECTION OUTPUT ;
    USE SIGNAL ;
    SHAPE ABUTMENT ;
    PORT
      LAYER M4 ;
      RECT 0 13.488 0.024 13.512 ;
    END
  END rw0_rd_out[16]
  PIN rw0_rd_out[17]
    DIRECTION OUTPUT ;
    USE SIGNAL ;
    SHAPE ABUTMENT ;
    PORT
      LAYER M4 ;
      RECT 0 13.536 0.024 13.56 ;
    END
  END rw0_rd_out[17]
  PIN rw0_rd_out[18]
    DIRECTION OUTPUT ;
    USE SIGNAL ;
    SHAPE ABUTMENT ;
    PORT
      LAYER M4 ;
      RECT 0 13.584 0.024 13.608 ;
    END
  END rw0_rd_out[18]
  PIN rw0_rd_out[19]
    DIRECTION OUTPUT ;
    USE SIGNAL ;
    SHAPE ABUTMENT ;
    PORT
      LAYER M4 ;
      RECT 0 13.632 0.024 13.656 ;
    END
  END rw0_rd_out[19]
  PIN rw0_rd_out[20]
    DIRECTION OUTPUT ;
    USE SIGNAL ;
    SHAPE ABUTMENT ;
    PORT
      LAYER M4 ;
      RECT 0 13.68 0.024 13.704 ;
    END
  END rw0_rd_out[20]
  PIN rw0_rd_out[21]
    DIRECTION OUTPUT ;
    USE SIGNAL ;
    SHAPE ABUTMENT ;
    PORT
      LAYER M4 ;
      RECT 0 13.728 0.024 13.752 ;
    END
  END rw0_rd_out[21]
  PIN rw0_rd_out[22]
    DIRECTION OUTPUT ;
    USE SIGNAL ;
    SHAPE ABUTMENT ;
    PORT
      LAYER M4 ;
      RECT 0 13.776 0.024 13.8 ;
    END
  END rw0_rd_out[22]
  PIN rw0_rd_out[23]
    DIRECTION OUTPUT ;
    USE SIGNAL ;
    SHAPE ABUTMENT ;
    PORT
      LAYER M4 ;
      RECT 0 13.824 0.024 13.848 ;
    END
  END rw0_rd_out[23]
  PIN rw0_rd_out[24]
    DIRECTION OUTPUT ;
    USE SIGNAL ;
    SHAPE ABUTMENT ;
    PORT
      LAYER M4 ;
      RECT 0 13.872 0.024 13.896 ;
    END
  END rw0_rd_out[24]
  PIN rw0_rd_out[25]
    DIRECTION OUTPUT ;
    USE SIGNAL ;
    SHAPE ABUTMENT ;
    PORT
      LAYER M4 ;
      RECT 0 13.92 0.024 13.944 ;
    END
  END rw0_rd_out[25]
  PIN rw0_rd_out[26]
    DIRECTION OUTPUT ;
    USE SIGNAL ;
    SHAPE ABUTMENT ;
    PORT
      LAYER M4 ;
      RECT 0 13.968 0.024 13.992 ;
    END
  END rw0_rd_out[26]
  PIN rw0_rd_out[27]
    DIRECTION OUTPUT ;
    USE SIGNAL ;
    SHAPE ABUTMENT ;
    PORT
      LAYER M4 ;
      RECT 0 14.016 0.024 14.04 ;
    END
  END rw0_rd_out[27]
  PIN rw0_rd_out[28]
    DIRECTION OUTPUT ;
    USE SIGNAL ;
    SHAPE ABUTMENT ;
    PORT
      LAYER M4 ;
      RECT 0 14.064 0.024 14.088 ;
    END
  END rw0_rd_out[28]
  PIN rw0_rd_out[29]
    DIRECTION OUTPUT ;
    USE SIGNAL ;
    SHAPE ABUTMENT ;
    PORT
      LAYER M4 ;
      RECT 0 14.112 0.024 14.136 ;
    END
  END rw0_rd_out[29]
  PIN rw0_rd_out[30]
    DIRECTION OUTPUT ;
    USE SIGNAL ;
    SHAPE ABUTMENT ;
    PORT
      LAYER M4 ;
      RECT 0 14.16 0.024 14.184 ;
    END
  END rw0_rd_out[30]
  PIN rw0_rd_out[31]
    DIRECTION OUTPUT ;
    USE SIGNAL ;
    SHAPE ABUTMENT ;
    PORT
      LAYER M4 ;
      RECT 0 14.208 0.024 14.232 ;
    END
  END rw0_rd_out[31]
  PIN rw0_rd_out[32]
    DIRECTION OUTPUT ;
    USE SIGNAL ;
    SHAPE ABUTMENT ;
    PORT
      LAYER M4 ;
      RECT 0 14.256 0.024 14.28 ;
    END
  END rw0_rd_out[32]
  PIN rw0_rd_out[33]
    DIRECTION OUTPUT ;
    USE SIGNAL ;
    SHAPE ABUTMENT ;
    PORT
      LAYER M4 ;
      RECT 0 14.304 0.024 14.328 ;
    END
  END rw0_rd_out[33]
  PIN rw0_rd_out[34]
    DIRECTION OUTPUT ;
    USE SIGNAL ;
    SHAPE ABUTMENT ;
    PORT
      LAYER M4 ;
      RECT 0 14.352 0.024 14.376 ;
    END
  END rw0_rd_out[34]
  PIN rw0_rd_out[35]
    DIRECTION OUTPUT ;
    USE SIGNAL ;
    SHAPE ABUTMENT ;
    PORT
      LAYER M4 ;
      RECT 0 14.4 0.024 14.424 ;
    END
  END rw0_rd_out[35]
  PIN rw0_rd_out[36]
    DIRECTION OUTPUT ;
    USE SIGNAL ;
    SHAPE ABUTMENT ;
    PORT
      LAYER M4 ;
      RECT 0 14.448 0.024 14.472 ;
    END
  END rw0_rd_out[36]
  PIN rw0_rd_out[37]
    DIRECTION OUTPUT ;
    USE SIGNAL ;
    SHAPE ABUTMENT ;
    PORT
      LAYER M4 ;
      RECT 0 14.496 0.024 14.52 ;
    END
  END rw0_rd_out[37]
  PIN rw0_rd_out[38]
    DIRECTION OUTPUT ;
    USE SIGNAL ;
    SHAPE ABUTMENT ;
    PORT
      LAYER M4 ;
      RECT 0 14.544 0.024 14.568 ;
    END
  END rw0_rd_out[38]
  PIN rw0_rd_out[39]
    DIRECTION OUTPUT ;
    USE SIGNAL ;
    SHAPE ABUTMENT ;
    PORT
      LAYER M4 ;
      RECT 0 14.592 0.024 14.616 ;
    END
  END rw0_rd_out[39]
  PIN rw0_rd_out[40]
    DIRECTION OUTPUT ;
    USE SIGNAL ;
    SHAPE ABUTMENT ;
    PORT
      LAYER M4 ;
      RECT 0 14.64 0.024 14.664 ;
    END
  END rw0_rd_out[40]
  PIN rw0_rd_out[41]
    DIRECTION OUTPUT ;
    USE SIGNAL ;
    SHAPE ABUTMENT ;
    PORT
      LAYER M4 ;
      RECT 0 14.688 0.024 14.712 ;
    END
  END rw0_rd_out[41]
  PIN rw0_rd_out[42]
    DIRECTION OUTPUT ;
    USE SIGNAL ;
    SHAPE ABUTMENT ;
    PORT
      LAYER M4 ;
      RECT 0 14.736 0.024 14.76 ;
    END
  END rw0_rd_out[42]
  PIN rw0_rd_out[43]
    DIRECTION OUTPUT ;
    USE SIGNAL ;
    SHAPE ABUTMENT ;
    PORT
      LAYER M4 ;
      RECT 0 14.784 0.024 14.808 ;
    END
  END rw0_rd_out[43]
  PIN rw0_rd_out[44]
    DIRECTION OUTPUT ;
    USE SIGNAL ;
    SHAPE ABUTMENT ;
    PORT
      LAYER M4 ;
      RECT 0 14.832 0.024 14.856 ;
    END
  END rw0_rd_out[44]
  PIN rw0_rd_out[45]
    DIRECTION OUTPUT ;
    USE SIGNAL ;
    SHAPE ABUTMENT ;
    PORT
      LAYER M4 ;
      RECT 0 14.88 0.024 14.904 ;
    END
  END rw0_rd_out[45]
  PIN rw0_rd_out[46]
    DIRECTION OUTPUT ;
    USE SIGNAL ;
    SHAPE ABUTMENT ;
    PORT
      LAYER M4 ;
      RECT 0 14.928 0.024 14.952 ;
    END
  END rw0_rd_out[46]
  PIN rw0_rd_out[47]
    DIRECTION OUTPUT ;
    USE SIGNAL ;
    SHAPE ABUTMENT ;
    PORT
      LAYER M4 ;
      RECT 0 14.976 0.024 15 ;
    END
  END rw0_rd_out[47]
  PIN rw0_rd_out[48]
    DIRECTION OUTPUT ;
    USE SIGNAL ;
    SHAPE ABUTMENT ;
    PORT
      LAYER M4 ;
      RECT 0 15.024 0.024 15.048 ;
    END
  END rw0_rd_out[48]
  PIN rw0_rd_out[49]
    DIRECTION OUTPUT ;
    USE SIGNAL ;
    SHAPE ABUTMENT ;
    PORT
      LAYER M4 ;
      RECT 0 15.072 0.024 15.096 ;
    END
  END rw0_rd_out[49]
  PIN rw0_rd_out[50]
    DIRECTION OUTPUT ;
    USE SIGNAL ;
    SHAPE ABUTMENT ;
    PORT
      LAYER M4 ;
      RECT 0 15.12 0.024 15.144 ;
    END
  END rw0_rd_out[50]
  PIN rw0_rd_out[51]
    DIRECTION OUTPUT ;
    USE SIGNAL ;
    SHAPE ABUTMENT ;
    PORT
      LAYER M4 ;
      RECT 0 15.168 0.024 15.192 ;
    END
  END rw0_rd_out[51]
  PIN rw0_rd_out[52]
    DIRECTION OUTPUT ;
    USE SIGNAL ;
    SHAPE ABUTMENT ;
    PORT
      LAYER M4 ;
      RECT 0 15.216 0.024 15.24 ;
    END
  END rw0_rd_out[52]
  PIN rw0_rd_out[53]
    DIRECTION OUTPUT ;
    USE SIGNAL ;
    SHAPE ABUTMENT ;
    PORT
      LAYER M4 ;
      RECT 0 15.264 0.024 15.288 ;
    END
  END rw0_rd_out[53]
  PIN rw0_rd_out[54]
    DIRECTION OUTPUT ;
    USE SIGNAL ;
    SHAPE ABUTMENT ;
    PORT
      LAYER M4 ;
      RECT 0 15.312 0.024 15.336 ;
    END
  END rw0_rd_out[54]
  PIN rw0_rd_out[55]
    DIRECTION OUTPUT ;
    USE SIGNAL ;
    SHAPE ABUTMENT ;
    PORT
      LAYER M4 ;
      RECT 0 15.36 0.024 15.384 ;
    END
  END rw0_rd_out[55]
  PIN rw0_rd_out[56]
    DIRECTION OUTPUT ;
    USE SIGNAL ;
    SHAPE ABUTMENT ;
    PORT
      LAYER M4 ;
      RECT 0 15.408 0.024 15.432 ;
    END
  END rw0_rd_out[56]
  PIN rw0_rd_out[57]
    DIRECTION OUTPUT ;
    USE SIGNAL ;
    SHAPE ABUTMENT ;
    PORT
      LAYER M4 ;
      RECT 0 15.456 0.024 15.48 ;
    END
  END rw0_rd_out[57]
  PIN rw0_rd_out[58]
    DIRECTION OUTPUT ;
    USE SIGNAL ;
    SHAPE ABUTMENT ;
    PORT
      LAYER M4 ;
      RECT 0 15.504 0.024 15.528 ;
    END
  END rw0_rd_out[58]
  PIN rw0_rd_out[59]
    DIRECTION OUTPUT ;
    USE SIGNAL ;
    SHAPE ABUTMENT ;
    PORT
      LAYER M4 ;
      RECT 0 15.552 0.024 15.576 ;
    END
  END rw0_rd_out[59]
  PIN rw0_rd_out[60]
    DIRECTION OUTPUT ;
    USE SIGNAL ;
    SHAPE ABUTMENT ;
    PORT
      LAYER M4 ;
      RECT 0 15.6 0.024 15.624 ;
    END
  END rw0_rd_out[60]
  PIN rw0_rd_out[61]
    DIRECTION OUTPUT ;
    USE SIGNAL ;
    SHAPE ABUTMENT ;
    PORT
      LAYER M4 ;
      RECT 0 15.648 0.024 15.672 ;
    END
  END rw0_rd_out[61]
  PIN rw0_rd_out[62]
    DIRECTION OUTPUT ;
    USE SIGNAL ;
    SHAPE ABUTMENT ;
    PORT
      LAYER M4 ;
      RECT 0 15.696 0.024 15.72 ;
    END
  END rw0_rd_out[62]
  PIN rw0_rd_out[63]
    DIRECTION OUTPUT ;
    USE SIGNAL ;
    SHAPE ABUTMENT ;
    PORT
      LAYER M4 ;
      RECT 0 15.744 0.024 15.768 ;
    END
  END rw0_rd_out[63]
  PIN rw0_rd_out[64]
    DIRECTION OUTPUT ;
    USE SIGNAL ;
    SHAPE ABUTMENT ;
    PORT
      LAYER M4 ;
      RECT 0 15.792 0.024 15.816 ;
    END
  END rw0_rd_out[64]
  PIN rw0_rd_out[65]
    DIRECTION OUTPUT ;
    USE SIGNAL ;
    SHAPE ABUTMENT ;
    PORT
      LAYER M4 ;
      RECT 0 15.84 0.024 15.864 ;
    END
  END rw0_rd_out[65]
  PIN rw0_rd_out[66]
    DIRECTION OUTPUT ;
    USE SIGNAL ;
    SHAPE ABUTMENT ;
    PORT
      LAYER M4 ;
      RECT 0 15.888 0.024 15.912 ;
    END
  END rw0_rd_out[66]
  PIN rw0_rd_out[67]
    DIRECTION OUTPUT ;
    USE SIGNAL ;
    SHAPE ABUTMENT ;
    PORT
      LAYER M4 ;
      RECT 0 15.936 0.024 15.96 ;
    END
  END rw0_rd_out[67]
  PIN rw0_rd_out[68]
    DIRECTION OUTPUT ;
    USE SIGNAL ;
    SHAPE ABUTMENT ;
    PORT
      LAYER M4 ;
      RECT 0 15.984 0.024 16.008 ;
    END
  END rw0_rd_out[68]
  PIN rw0_rd_out[69]
    DIRECTION OUTPUT ;
    USE SIGNAL ;
    SHAPE ABUTMENT ;
    PORT
      LAYER M4 ;
      RECT 0 16.032 0.024 16.056 ;
    END
  END rw0_rd_out[69]
  PIN rw0_rd_out[70]
    DIRECTION OUTPUT ;
    USE SIGNAL ;
    SHAPE ABUTMENT ;
    PORT
      LAYER M4 ;
      RECT 0 16.08 0.024 16.104 ;
    END
  END rw0_rd_out[70]
  PIN rw0_rd_out[71]
    DIRECTION OUTPUT ;
    USE SIGNAL ;
    SHAPE ABUTMENT ;
    PORT
      LAYER M4 ;
      RECT 0 16.128 0.024 16.152 ;
    END
  END rw0_rd_out[71]
  PIN rw0_rd_out[72]
    DIRECTION OUTPUT ;
    USE SIGNAL ;
    SHAPE ABUTMENT ;
    PORT
      LAYER M4 ;
      RECT 0 16.176 0.024 16.2 ;
    END
  END rw0_rd_out[72]
  PIN rw0_rd_out[73]
    DIRECTION OUTPUT ;
    USE SIGNAL ;
    SHAPE ABUTMENT ;
    PORT
      LAYER M4 ;
      RECT 0 16.224 0.024 16.248 ;
    END
  END rw0_rd_out[73]
  PIN rw0_rd_out[74]
    DIRECTION OUTPUT ;
    USE SIGNAL ;
    SHAPE ABUTMENT ;
    PORT
      LAYER M4 ;
      RECT 0 16.272 0.024 16.296 ;
    END
  END rw0_rd_out[74]
  PIN rw0_rd_out[75]
    DIRECTION OUTPUT ;
    USE SIGNAL ;
    SHAPE ABUTMENT ;
    PORT
      LAYER M4 ;
      RECT 0 16.32 0.024 16.344 ;
    END
  END rw0_rd_out[75]
  PIN rw0_rd_out[76]
    DIRECTION OUTPUT ;
    USE SIGNAL ;
    SHAPE ABUTMENT ;
    PORT
      LAYER M4 ;
      RECT 0 16.368 0.024 16.392 ;
    END
  END rw0_rd_out[76]
  PIN rw0_rd_out[77]
    DIRECTION OUTPUT ;
    USE SIGNAL ;
    SHAPE ABUTMENT ;
    PORT
      LAYER M4 ;
      RECT 0 16.416 0.024 16.44 ;
    END
  END rw0_rd_out[77]
  PIN rw0_rd_out[78]
    DIRECTION OUTPUT ;
    USE SIGNAL ;
    SHAPE ABUTMENT ;
    PORT
      LAYER M4 ;
      RECT 0 16.464 0.024 16.488 ;
    END
  END rw0_rd_out[78]
  PIN rw0_rd_out[79]
    DIRECTION OUTPUT ;
    USE SIGNAL ;
    SHAPE ABUTMENT ;
    PORT
      LAYER M4 ;
      RECT 0 16.512 0.024 16.536 ;
    END
  END rw0_rd_out[79]
  PIN rw0_rd_out[80]
    DIRECTION OUTPUT ;
    USE SIGNAL ;
    SHAPE ABUTMENT ;
    PORT
      LAYER M4 ;
      RECT 0 16.56 0.024 16.584 ;
    END
  END rw0_rd_out[80]
  PIN rw0_rd_out[81]
    DIRECTION OUTPUT ;
    USE SIGNAL ;
    SHAPE ABUTMENT ;
    PORT
      LAYER M4 ;
      RECT 0 16.608 0.024 16.632 ;
    END
  END rw0_rd_out[81]
  PIN rw0_rd_out[82]
    DIRECTION OUTPUT ;
    USE SIGNAL ;
    SHAPE ABUTMENT ;
    PORT
      LAYER M4 ;
      RECT 0 16.656 0.024 16.68 ;
    END
  END rw0_rd_out[82]
  PIN rw0_rd_out[83]
    DIRECTION OUTPUT ;
    USE SIGNAL ;
    SHAPE ABUTMENT ;
    PORT
      LAYER M4 ;
      RECT 0 16.704 0.024 16.728 ;
    END
  END rw0_rd_out[83]
  PIN rw0_rd_out[84]
    DIRECTION OUTPUT ;
    USE SIGNAL ;
    SHAPE ABUTMENT ;
    PORT
      LAYER M4 ;
      RECT 0 16.752 0.024 16.776 ;
    END
  END rw0_rd_out[84]
  PIN rw0_rd_out[85]
    DIRECTION OUTPUT ;
    USE SIGNAL ;
    SHAPE ABUTMENT ;
    PORT
      LAYER M4 ;
      RECT 0 16.8 0.024 16.824 ;
    END
  END rw0_rd_out[85]
  PIN rw0_rd_out[86]
    DIRECTION OUTPUT ;
    USE SIGNAL ;
    SHAPE ABUTMENT ;
    PORT
      LAYER M4 ;
      RECT 0 16.848 0.024 16.872 ;
    END
  END rw0_rd_out[86]
  PIN rw0_rd_out[87]
    DIRECTION OUTPUT ;
    USE SIGNAL ;
    SHAPE ABUTMENT ;
    PORT
      LAYER M4 ;
      RECT 0 16.896 0.024 16.92 ;
    END
  END rw0_rd_out[87]
  PIN rw0_rd_out[88]
    DIRECTION OUTPUT ;
    USE SIGNAL ;
    SHAPE ABUTMENT ;
    PORT
      LAYER M4 ;
      RECT 0 16.944 0.024 16.968 ;
    END
  END rw0_rd_out[88]
  PIN rw0_rd_out[89]
    DIRECTION OUTPUT ;
    USE SIGNAL ;
    SHAPE ABUTMENT ;
    PORT
      LAYER M4 ;
      RECT 0 16.992 0.024 17.016 ;
    END
  END rw0_rd_out[89]
  PIN rw0_rd_out[90]
    DIRECTION OUTPUT ;
    USE SIGNAL ;
    SHAPE ABUTMENT ;
    PORT
      LAYER M4 ;
      RECT 0 17.04 0.024 17.064 ;
    END
  END rw0_rd_out[90]
  PIN rw0_rd_out[91]
    DIRECTION OUTPUT ;
    USE SIGNAL ;
    SHAPE ABUTMENT ;
    PORT
      LAYER M4 ;
      RECT 0 17.088 0.024 17.112 ;
    END
  END rw0_rd_out[91]
  PIN rw0_rd_out[92]
    DIRECTION OUTPUT ;
    USE SIGNAL ;
    SHAPE ABUTMENT ;
    PORT
      LAYER M4 ;
      RECT 0 17.136 0.024 17.16 ;
    END
  END rw0_rd_out[92]
  PIN rw0_rd_out[93]
    DIRECTION OUTPUT ;
    USE SIGNAL ;
    SHAPE ABUTMENT ;
    PORT
      LAYER M4 ;
      RECT 0 17.184 0.024 17.208 ;
    END
  END rw0_rd_out[93]
  PIN rw0_rd_out[94]
    DIRECTION OUTPUT ;
    USE SIGNAL ;
    SHAPE ABUTMENT ;
    PORT
      LAYER M4 ;
      RECT 0 17.232 0.024 17.256 ;
    END
  END rw0_rd_out[94]
  PIN rw0_rd_out[95]
    DIRECTION OUTPUT ;
    USE SIGNAL ;
    SHAPE ABUTMENT ;
    PORT
      LAYER M4 ;
      RECT 0 17.28 0.024 17.304 ;
    END
  END rw0_rd_out[95]
  PIN rw0_rd_out[96]
    DIRECTION OUTPUT ;
    USE SIGNAL ;
    SHAPE ABUTMENT ;
    PORT
      LAYER M4 ;
      RECT 0 17.328 0.024 17.352 ;
    END
  END rw0_rd_out[96]
  PIN rw0_rd_out[97]
    DIRECTION OUTPUT ;
    USE SIGNAL ;
    SHAPE ABUTMENT ;
    PORT
      LAYER M4 ;
      RECT 0 17.376 0.024 17.4 ;
    END
  END rw0_rd_out[97]
  PIN rw0_rd_out[98]
    DIRECTION OUTPUT ;
    USE SIGNAL ;
    SHAPE ABUTMENT ;
    PORT
      LAYER M4 ;
      RECT 0 17.424 0.024 17.448 ;
    END
  END rw0_rd_out[98]
  PIN rw0_rd_out[99]
    DIRECTION OUTPUT ;
    USE SIGNAL ;
    SHAPE ABUTMENT ;
    PORT
      LAYER M4 ;
      RECT 0 17.472 0.024 17.496 ;
    END
  END rw0_rd_out[99]
  PIN rw0_rd_out[100]
    DIRECTION OUTPUT ;
    USE SIGNAL ;
    SHAPE ABUTMENT ;
    PORT
      LAYER M4 ;
      RECT 0 17.52 0.024 17.544 ;
    END
  END rw0_rd_out[100]
  PIN rw0_rd_out[101]
    DIRECTION OUTPUT ;
    USE SIGNAL ;
    SHAPE ABUTMENT ;
    PORT
      LAYER M4 ;
      RECT 0 17.568 0.024 17.592 ;
    END
  END rw0_rd_out[101]
  PIN rw0_rd_out[102]
    DIRECTION OUTPUT ;
    USE SIGNAL ;
    SHAPE ABUTMENT ;
    PORT
      LAYER M4 ;
      RECT 0 17.616 0.024 17.64 ;
    END
  END rw0_rd_out[102]
  PIN rw0_rd_out[103]
    DIRECTION OUTPUT ;
    USE SIGNAL ;
    SHAPE ABUTMENT ;
    PORT
      LAYER M4 ;
      RECT 0 17.664 0.024 17.688 ;
    END
  END rw0_rd_out[103]
  PIN rw0_rd_out[104]
    DIRECTION OUTPUT ;
    USE SIGNAL ;
    SHAPE ABUTMENT ;
    PORT
      LAYER M4 ;
      RECT 0 17.712 0.024 17.736 ;
    END
  END rw0_rd_out[104]
  PIN rw0_rd_out[105]
    DIRECTION OUTPUT ;
    USE SIGNAL ;
    SHAPE ABUTMENT ;
    PORT
      LAYER M4 ;
      RECT 0 17.76 0.024 17.784 ;
    END
  END rw0_rd_out[105]
  PIN rw0_rd_out[106]
    DIRECTION OUTPUT ;
    USE SIGNAL ;
    SHAPE ABUTMENT ;
    PORT
      LAYER M4 ;
      RECT 0 17.808 0.024 17.832 ;
    END
  END rw0_rd_out[106]
  PIN rw0_rd_out[107]
    DIRECTION OUTPUT ;
    USE SIGNAL ;
    SHAPE ABUTMENT ;
    PORT
      LAYER M4 ;
      RECT 0 17.856 0.024 17.88 ;
    END
  END rw0_rd_out[107]
  PIN rw0_rd_out[108]
    DIRECTION OUTPUT ;
    USE SIGNAL ;
    SHAPE ABUTMENT ;
    PORT
      LAYER M4 ;
      RECT 0 17.904 0.024 17.928 ;
    END
  END rw0_rd_out[108]
  PIN rw0_rd_out[109]
    DIRECTION OUTPUT ;
    USE SIGNAL ;
    SHAPE ABUTMENT ;
    PORT
      LAYER M4 ;
      RECT 0 17.952 0.024 17.976 ;
    END
  END rw0_rd_out[109]
  PIN rw0_rd_out[110]
    DIRECTION OUTPUT ;
    USE SIGNAL ;
    SHAPE ABUTMENT ;
    PORT
      LAYER M4 ;
      RECT 0 18 0.024 18.024 ;
    END
  END rw0_rd_out[110]
  PIN rw0_rd_out[111]
    DIRECTION OUTPUT ;
    USE SIGNAL ;
    SHAPE ABUTMENT ;
    PORT
      LAYER M4 ;
      RECT 0 18.048 0.024 18.072 ;
    END
  END rw0_rd_out[111]
  PIN rw0_rd_out[112]
    DIRECTION OUTPUT ;
    USE SIGNAL ;
    SHAPE ABUTMENT ;
    PORT
      LAYER M4 ;
      RECT 0 18.096 0.024 18.12 ;
    END
  END rw0_rd_out[112]
  PIN rw0_rd_out[113]
    DIRECTION OUTPUT ;
    USE SIGNAL ;
    SHAPE ABUTMENT ;
    PORT
      LAYER M4 ;
      RECT 0 18.144 0.024 18.168 ;
    END
  END rw0_rd_out[113]
  PIN rw0_rd_out[114]
    DIRECTION OUTPUT ;
    USE SIGNAL ;
    SHAPE ABUTMENT ;
    PORT
      LAYER M4 ;
      RECT 0 18.192 0.024 18.216 ;
    END
  END rw0_rd_out[114]
  PIN rw0_rd_out[115]
    DIRECTION OUTPUT ;
    USE SIGNAL ;
    SHAPE ABUTMENT ;
    PORT
      LAYER M4 ;
      RECT 0 18.24 0.024 18.264 ;
    END
  END rw0_rd_out[115]
  PIN rw0_rd_out[116]
    DIRECTION OUTPUT ;
    USE SIGNAL ;
    SHAPE ABUTMENT ;
    PORT
      LAYER M4 ;
      RECT 0 18.288 0.024 18.312 ;
    END
  END rw0_rd_out[116]
  PIN rw0_rd_out[117]
    DIRECTION OUTPUT ;
    USE SIGNAL ;
    SHAPE ABUTMENT ;
    PORT
      LAYER M4 ;
      RECT 0 18.336 0.024 18.36 ;
    END
  END rw0_rd_out[117]
  PIN rw0_rd_out[118]
    DIRECTION OUTPUT ;
    USE SIGNAL ;
    SHAPE ABUTMENT ;
    PORT
      LAYER M4 ;
      RECT 0 18.384 0.024 18.408 ;
    END
  END rw0_rd_out[118]
  PIN rw0_rd_out[119]
    DIRECTION OUTPUT ;
    USE SIGNAL ;
    SHAPE ABUTMENT ;
    PORT
      LAYER M4 ;
      RECT 0 18.432 0.024 18.456 ;
    END
  END rw0_rd_out[119]
  PIN rw0_rd_out[120]
    DIRECTION OUTPUT ;
    USE SIGNAL ;
    SHAPE ABUTMENT ;
    PORT
      LAYER M4 ;
      RECT 0 18.48 0.024 18.504 ;
    END
  END rw0_rd_out[120]
  PIN rw0_rd_out[121]
    DIRECTION OUTPUT ;
    USE SIGNAL ;
    SHAPE ABUTMENT ;
    PORT
      LAYER M4 ;
      RECT 0 18.528 0.024 18.552 ;
    END
  END rw0_rd_out[121]
  PIN rw0_rd_out[122]
    DIRECTION OUTPUT ;
    USE SIGNAL ;
    SHAPE ABUTMENT ;
    PORT
      LAYER M4 ;
      RECT 0 18.576 0.024 18.6 ;
    END
  END rw0_rd_out[122]
  PIN rw0_rd_out[123]
    DIRECTION OUTPUT ;
    USE SIGNAL ;
    SHAPE ABUTMENT ;
    PORT
      LAYER M4 ;
      RECT 0 18.624 0.024 18.648 ;
    END
  END rw0_rd_out[123]
  PIN rw0_rd_out[124]
    DIRECTION OUTPUT ;
    USE SIGNAL ;
    SHAPE ABUTMENT ;
    PORT
      LAYER M4 ;
      RECT 0 18.672 0.024 18.696 ;
    END
  END rw0_rd_out[124]
  PIN rw0_rd_out[125]
    DIRECTION OUTPUT ;
    USE SIGNAL ;
    SHAPE ABUTMENT ;
    PORT
      LAYER M4 ;
      RECT 0 18.72 0.024 18.744 ;
    END
  END rw0_rd_out[125]
  PIN rw0_rd_out[126]
    DIRECTION OUTPUT ;
    USE SIGNAL ;
    SHAPE ABUTMENT ;
    PORT
      LAYER M4 ;
      RECT 0 18.768 0.024 18.792 ;
    END
  END rw0_rd_out[126]
  PIN rw0_rd_out[127]
    DIRECTION OUTPUT ;
    USE SIGNAL ;
    SHAPE ABUTMENT ;
    PORT
      LAYER M4 ;
      RECT 0 18.816 0.024 18.84 ;
    END
  END rw0_rd_out[127]
  PIN rw0_rd_out[128]
    DIRECTION OUTPUT ;
    USE SIGNAL ;
    SHAPE ABUTMENT ;
    PORT
      LAYER M4 ;
      RECT 0 18.864 0.024 18.888 ;
    END
  END rw0_rd_out[128]
  PIN rw0_rd_out[129]
    DIRECTION OUTPUT ;
    USE SIGNAL ;
    SHAPE ABUTMENT ;
    PORT
      LAYER M4 ;
      RECT 0 18.912 0.024 18.936 ;
    END
  END rw0_rd_out[129]
  PIN rw0_rd_out[130]
    DIRECTION OUTPUT ;
    USE SIGNAL ;
    SHAPE ABUTMENT ;
    PORT
      LAYER M4 ;
      RECT 0 18.96 0.024 18.984 ;
    END
  END rw0_rd_out[130]
  PIN rw0_rd_out[131]
    DIRECTION OUTPUT ;
    USE SIGNAL ;
    SHAPE ABUTMENT ;
    PORT
      LAYER M4 ;
      RECT 0 19.008 0.024 19.032 ;
    END
  END rw0_rd_out[131]
  PIN rw0_rd_out[132]
    DIRECTION OUTPUT ;
    USE SIGNAL ;
    SHAPE ABUTMENT ;
    PORT
      LAYER M4 ;
      RECT 0 19.056 0.024 19.08 ;
    END
  END rw0_rd_out[132]
  PIN rw0_rd_out[133]
    DIRECTION OUTPUT ;
    USE SIGNAL ;
    SHAPE ABUTMENT ;
    PORT
      LAYER M4 ;
      RECT 0 19.104 0.024 19.128 ;
    END
  END rw0_rd_out[133]
  PIN rw0_rd_out[134]
    DIRECTION OUTPUT ;
    USE SIGNAL ;
    SHAPE ABUTMENT ;
    PORT
      LAYER M4 ;
      RECT 0 19.152 0.024 19.176 ;
    END
  END rw0_rd_out[134]
  PIN rw0_rd_out[135]
    DIRECTION OUTPUT ;
    USE SIGNAL ;
    SHAPE ABUTMENT ;
    PORT
      LAYER M4 ;
      RECT 0 19.2 0.024 19.224 ;
    END
  END rw0_rd_out[135]
  PIN rw0_rd_out[136]
    DIRECTION OUTPUT ;
    USE SIGNAL ;
    SHAPE ABUTMENT ;
    PORT
      LAYER M4 ;
      RECT 0 19.248 0.024 19.272 ;
    END
  END rw0_rd_out[136]
  PIN rw0_rd_out[137]
    DIRECTION OUTPUT ;
    USE SIGNAL ;
    SHAPE ABUTMENT ;
    PORT
      LAYER M4 ;
      RECT 0 19.296 0.024 19.32 ;
    END
  END rw0_rd_out[137]
  PIN rw0_rd_out[138]
    DIRECTION OUTPUT ;
    USE SIGNAL ;
    SHAPE ABUTMENT ;
    PORT
      LAYER M4 ;
      RECT 0 19.344 0.024 19.368 ;
    END
  END rw0_rd_out[138]
  PIN rw0_rd_out[139]
    DIRECTION OUTPUT ;
    USE SIGNAL ;
    SHAPE ABUTMENT ;
    PORT
      LAYER M4 ;
      RECT 0 19.392 0.024 19.416 ;
    END
  END rw0_rd_out[139]
  PIN rw0_rd_out[140]
    DIRECTION OUTPUT ;
    USE SIGNAL ;
    SHAPE ABUTMENT ;
    PORT
      LAYER M4 ;
      RECT 0 19.44 0.024 19.464 ;
    END
  END rw0_rd_out[140]
  PIN rw0_rd_out[141]
    DIRECTION OUTPUT ;
    USE SIGNAL ;
    SHAPE ABUTMENT ;
    PORT
      LAYER M4 ;
      RECT 0 19.488 0.024 19.512 ;
    END
  END rw0_rd_out[141]
  PIN rw0_rd_out[142]
    DIRECTION OUTPUT ;
    USE SIGNAL ;
    SHAPE ABUTMENT ;
    PORT
      LAYER M4 ;
      RECT 0 19.536 0.024 19.56 ;
    END
  END rw0_rd_out[142]
  PIN rw0_rd_out[143]
    DIRECTION OUTPUT ;
    USE SIGNAL ;
    SHAPE ABUTMENT ;
    PORT
      LAYER M4 ;
      RECT 0 19.584 0.024 19.608 ;
    END
  END rw0_rd_out[143]
  PIN rw0_rd_out[144]
    DIRECTION OUTPUT ;
    USE SIGNAL ;
    SHAPE ABUTMENT ;
    PORT
      LAYER M4 ;
      RECT 0 19.632 0.024 19.656 ;
    END
  END rw0_rd_out[144]
  PIN rw0_rd_out[145]
    DIRECTION OUTPUT ;
    USE SIGNAL ;
    SHAPE ABUTMENT ;
    PORT
      LAYER M4 ;
      RECT 0 19.68 0.024 19.704 ;
    END
  END rw0_rd_out[145]
  PIN rw0_rd_out[146]
    DIRECTION OUTPUT ;
    USE SIGNAL ;
    SHAPE ABUTMENT ;
    PORT
      LAYER M4 ;
      RECT 0 19.728 0.024 19.752 ;
    END
  END rw0_rd_out[146]
  PIN rw0_rd_out[147]
    DIRECTION OUTPUT ;
    USE SIGNAL ;
    SHAPE ABUTMENT ;
    PORT
      LAYER M4 ;
      RECT 0 19.776 0.024 19.8 ;
    END
  END rw0_rd_out[147]
  PIN rw0_rd_out[148]
    DIRECTION OUTPUT ;
    USE SIGNAL ;
    SHAPE ABUTMENT ;
    PORT
      LAYER M4 ;
      RECT 0 19.824 0.024 19.848 ;
    END
  END rw0_rd_out[148]
  PIN rw0_rd_out[149]
    DIRECTION OUTPUT ;
    USE SIGNAL ;
    SHAPE ABUTMENT ;
    PORT
      LAYER M4 ;
      RECT 0 19.872 0.024 19.896 ;
    END
  END rw0_rd_out[149]
  PIN rw0_rd_out[150]
    DIRECTION OUTPUT ;
    USE SIGNAL ;
    SHAPE ABUTMENT ;
    PORT
      LAYER M4 ;
      RECT 0 19.92 0.024 19.944 ;
    END
  END rw0_rd_out[150]
  PIN rw0_rd_out[151]
    DIRECTION OUTPUT ;
    USE SIGNAL ;
    SHAPE ABUTMENT ;
    PORT
      LAYER M4 ;
      RECT 0 19.968 0.024 19.992 ;
    END
  END rw0_rd_out[151]
  PIN rw0_rd_out[152]
    DIRECTION OUTPUT ;
    USE SIGNAL ;
    SHAPE ABUTMENT ;
    PORT
      LAYER M4 ;
      RECT 0 20.016 0.024 20.04 ;
    END
  END rw0_rd_out[152]
  PIN rw0_rd_out[153]
    DIRECTION OUTPUT ;
    USE SIGNAL ;
    SHAPE ABUTMENT ;
    PORT
      LAYER M4 ;
      RECT 0 20.064 0.024 20.088 ;
    END
  END rw0_rd_out[153]
  PIN rw0_rd_out[154]
    DIRECTION OUTPUT ;
    USE SIGNAL ;
    SHAPE ABUTMENT ;
    PORT
      LAYER M4 ;
      RECT 0 20.112 0.024 20.136 ;
    END
  END rw0_rd_out[154]
  PIN rw0_rd_out[155]
    DIRECTION OUTPUT ;
    USE SIGNAL ;
    SHAPE ABUTMENT ;
    PORT
      LAYER M4 ;
      RECT 0 20.16 0.024 20.184 ;
    END
  END rw0_rd_out[155]
  PIN rw0_rd_out[156]
    DIRECTION OUTPUT ;
    USE SIGNAL ;
    SHAPE ABUTMENT ;
    PORT
      LAYER M4 ;
      RECT 0 20.208 0.024 20.232 ;
    END
  END rw0_rd_out[156]
  PIN rw0_rd_out[157]
    DIRECTION OUTPUT ;
    USE SIGNAL ;
    SHAPE ABUTMENT ;
    PORT
      LAYER M4 ;
      RECT 0 20.256 0.024 20.28 ;
    END
  END rw0_rd_out[157]
  PIN rw0_rd_out[158]
    DIRECTION OUTPUT ;
    USE SIGNAL ;
    SHAPE ABUTMENT ;
    PORT
      LAYER M4 ;
      RECT 0 20.304 0.024 20.328 ;
    END
  END rw0_rd_out[158]
  PIN rw0_rd_out[159]
    DIRECTION OUTPUT ;
    USE SIGNAL ;
    SHAPE ABUTMENT ;
    PORT
      LAYER M4 ;
      RECT 0 20.352 0.024 20.376 ;
    END
  END rw0_rd_out[159]
  PIN rw0_rd_out[160]
    DIRECTION OUTPUT ;
    USE SIGNAL ;
    SHAPE ABUTMENT ;
    PORT
      LAYER M4 ;
      RECT 0 20.4 0.024 20.424 ;
    END
  END rw0_rd_out[160]
  PIN rw0_rd_out[161]
    DIRECTION OUTPUT ;
    USE SIGNAL ;
    SHAPE ABUTMENT ;
    PORT
      LAYER M4 ;
      RECT 0 20.448 0.024 20.472 ;
    END
  END rw0_rd_out[161]
  PIN rw0_rd_out[162]
    DIRECTION OUTPUT ;
    USE SIGNAL ;
    SHAPE ABUTMENT ;
    PORT
      LAYER M4 ;
      RECT 0 20.496 0.024 20.52 ;
    END
  END rw0_rd_out[162]
  PIN rw0_rd_out[163]
    DIRECTION OUTPUT ;
    USE SIGNAL ;
    SHAPE ABUTMENT ;
    PORT
      LAYER M4 ;
      RECT 0 20.544 0.024 20.568 ;
    END
  END rw0_rd_out[163]
  PIN rw0_rd_out[164]
    DIRECTION OUTPUT ;
    USE SIGNAL ;
    SHAPE ABUTMENT ;
    PORT
      LAYER M4 ;
      RECT 0 20.592 0.024 20.616 ;
    END
  END rw0_rd_out[164]
  PIN rw0_rd_out[165]
    DIRECTION OUTPUT ;
    USE SIGNAL ;
    SHAPE ABUTMENT ;
    PORT
      LAYER M4 ;
      RECT 0 20.64 0.024 20.664 ;
    END
  END rw0_rd_out[165]
  PIN rw0_rd_out[166]
    DIRECTION OUTPUT ;
    USE SIGNAL ;
    SHAPE ABUTMENT ;
    PORT
      LAYER M4 ;
      RECT 0 20.688 0.024 20.712 ;
    END
  END rw0_rd_out[166]
  PIN rw0_rd_out[167]
    DIRECTION OUTPUT ;
    USE SIGNAL ;
    SHAPE ABUTMENT ;
    PORT
      LAYER M4 ;
      RECT 0 20.736 0.024 20.76 ;
    END
  END rw0_rd_out[167]
  PIN rw0_rd_out[168]
    DIRECTION OUTPUT ;
    USE SIGNAL ;
    SHAPE ABUTMENT ;
    PORT
      LAYER M4 ;
      RECT 0 20.784 0.024 20.808 ;
    END
  END rw0_rd_out[168]
  PIN rw0_rd_out[169]
    DIRECTION OUTPUT ;
    USE SIGNAL ;
    SHAPE ABUTMENT ;
    PORT
      LAYER M4 ;
      RECT 0 20.832 0.024 20.856 ;
    END
  END rw0_rd_out[169]
  PIN rw0_rd_out[170]
    DIRECTION OUTPUT ;
    USE SIGNAL ;
    SHAPE ABUTMENT ;
    PORT
      LAYER M4 ;
      RECT 0 20.88 0.024 20.904 ;
    END
  END rw0_rd_out[170]
  PIN rw0_rd_out[171]
    DIRECTION OUTPUT ;
    USE SIGNAL ;
    SHAPE ABUTMENT ;
    PORT
      LAYER M4 ;
      RECT 0 20.928 0.024 20.952 ;
    END
  END rw0_rd_out[171]
  PIN rw0_rd_out[172]
    DIRECTION OUTPUT ;
    USE SIGNAL ;
    SHAPE ABUTMENT ;
    PORT
      LAYER M4 ;
      RECT 0 20.976 0.024 21 ;
    END
  END rw0_rd_out[172]
  PIN rw0_rd_out[173]
    DIRECTION OUTPUT ;
    USE SIGNAL ;
    SHAPE ABUTMENT ;
    PORT
      LAYER M4 ;
      RECT 0 21.024 0.024 21.048 ;
    END
  END rw0_rd_out[173]
  PIN rw0_rd_out[174]
    DIRECTION OUTPUT ;
    USE SIGNAL ;
    SHAPE ABUTMENT ;
    PORT
      LAYER M4 ;
      RECT 0 21.072 0.024 21.096 ;
    END
  END rw0_rd_out[174]
  PIN rw0_rd_out[175]
    DIRECTION OUTPUT ;
    USE SIGNAL ;
    SHAPE ABUTMENT ;
    PORT
      LAYER M4 ;
      RECT 0 21.12 0.024 21.144 ;
    END
  END rw0_rd_out[175]
  PIN rw0_rd_out[176]
    DIRECTION OUTPUT ;
    USE SIGNAL ;
    SHAPE ABUTMENT ;
    PORT
      LAYER M4 ;
      RECT 0 21.168 0.024 21.192 ;
    END
  END rw0_rd_out[176]
  PIN rw0_rd_out[177]
    DIRECTION OUTPUT ;
    USE SIGNAL ;
    SHAPE ABUTMENT ;
    PORT
      LAYER M4 ;
      RECT 0 21.216 0.024 21.24 ;
    END
  END rw0_rd_out[177]
  PIN rw0_rd_out[178]
    DIRECTION OUTPUT ;
    USE SIGNAL ;
    SHAPE ABUTMENT ;
    PORT
      LAYER M4 ;
      RECT 0 21.264 0.024 21.288 ;
    END
  END rw0_rd_out[178]
  PIN rw0_rd_out[179]
    DIRECTION OUTPUT ;
    USE SIGNAL ;
    SHAPE ABUTMENT ;
    PORT
      LAYER M4 ;
      RECT 0 21.312 0.024 21.336 ;
    END
  END rw0_rd_out[179]
  PIN rw0_rd_out[180]
    DIRECTION OUTPUT ;
    USE SIGNAL ;
    SHAPE ABUTMENT ;
    PORT
      LAYER M4 ;
      RECT 0 21.36 0.024 21.384 ;
    END
  END rw0_rd_out[180]
  PIN rw0_rd_out[181]
    DIRECTION OUTPUT ;
    USE SIGNAL ;
    SHAPE ABUTMENT ;
    PORT
      LAYER M4 ;
      RECT 0 21.408 0.024 21.432 ;
    END
  END rw0_rd_out[181]
  PIN rw0_rd_out[182]
    DIRECTION OUTPUT ;
    USE SIGNAL ;
    SHAPE ABUTMENT ;
    PORT
      LAYER M4 ;
      RECT 0 21.456 0.024 21.48 ;
    END
  END rw0_rd_out[182]
  PIN rw0_rd_out[183]
    DIRECTION OUTPUT ;
    USE SIGNAL ;
    SHAPE ABUTMENT ;
    PORT
      LAYER M4 ;
      RECT 0 21.504 0.024 21.528 ;
    END
  END rw0_rd_out[183]
  PIN rw0_rd_out[184]
    DIRECTION OUTPUT ;
    USE SIGNAL ;
    SHAPE ABUTMENT ;
    PORT
      LAYER M4 ;
      RECT 0 21.552 0.024 21.576 ;
    END
  END rw0_rd_out[184]
  PIN rw0_rd_out[185]
    DIRECTION OUTPUT ;
    USE SIGNAL ;
    SHAPE ABUTMENT ;
    PORT
      LAYER M4 ;
      RECT 0 21.6 0.024 21.624 ;
    END
  END rw0_rd_out[185]
  PIN rw0_rd_out[186]
    DIRECTION OUTPUT ;
    USE SIGNAL ;
    SHAPE ABUTMENT ;
    PORT
      LAYER M4 ;
      RECT 0 21.648 0.024 21.672 ;
    END
  END rw0_rd_out[186]
  PIN rw0_rd_out[187]
    DIRECTION OUTPUT ;
    USE SIGNAL ;
    SHAPE ABUTMENT ;
    PORT
      LAYER M4 ;
      RECT 0 21.696 0.024 21.72 ;
    END
  END rw0_rd_out[187]
  PIN rw0_rd_out[188]
    DIRECTION OUTPUT ;
    USE SIGNAL ;
    SHAPE ABUTMENT ;
    PORT
      LAYER M4 ;
      RECT 0 21.744 0.024 21.768 ;
    END
  END rw0_rd_out[188]
  PIN rw0_rd_out[189]
    DIRECTION OUTPUT ;
    USE SIGNAL ;
    SHAPE ABUTMENT ;
    PORT
      LAYER M4 ;
      RECT 0 21.792 0.024 21.816 ;
    END
  END rw0_rd_out[189]
  PIN rw0_rd_out[190]
    DIRECTION OUTPUT ;
    USE SIGNAL ;
    SHAPE ABUTMENT ;
    PORT
      LAYER M4 ;
      RECT 0 21.84 0.024 21.864 ;
    END
  END rw0_rd_out[190]
  PIN rw0_rd_out[191]
    DIRECTION OUTPUT ;
    USE SIGNAL ;
    SHAPE ABUTMENT ;
    PORT
      LAYER M4 ;
      RECT 0 21.888 0.024 21.912 ;
    END
  END rw0_rd_out[191]
  PIN rw0_rd_out[192]
    DIRECTION OUTPUT ;
    USE SIGNAL ;
    SHAPE ABUTMENT ;
    PORT
      LAYER M4 ;
      RECT 0 21.936 0.024 21.96 ;
    END
  END rw0_rd_out[192]
  PIN rw0_rd_out[193]
    DIRECTION OUTPUT ;
    USE SIGNAL ;
    SHAPE ABUTMENT ;
    PORT
      LAYER M4 ;
      RECT 0 21.984 0.024 22.008 ;
    END
  END rw0_rd_out[193]
  PIN rw0_rd_out[194]
    DIRECTION OUTPUT ;
    USE SIGNAL ;
    SHAPE ABUTMENT ;
    PORT
      LAYER M4 ;
      RECT 0 22.032 0.024 22.056 ;
    END
  END rw0_rd_out[194]
  PIN rw0_rd_out[195]
    DIRECTION OUTPUT ;
    USE SIGNAL ;
    SHAPE ABUTMENT ;
    PORT
      LAYER M4 ;
      RECT 0 22.08 0.024 22.104 ;
    END
  END rw0_rd_out[195]
  PIN rw0_rd_out[196]
    DIRECTION OUTPUT ;
    USE SIGNAL ;
    SHAPE ABUTMENT ;
    PORT
      LAYER M4 ;
      RECT 0 22.128 0.024 22.152 ;
    END
  END rw0_rd_out[196]
  PIN rw0_rd_out[197]
    DIRECTION OUTPUT ;
    USE SIGNAL ;
    SHAPE ABUTMENT ;
    PORT
      LAYER M4 ;
      RECT 0 22.176 0.024 22.2 ;
    END
  END rw0_rd_out[197]
  PIN rw0_rd_out[198]
    DIRECTION OUTPUT ;
    USE SIGNAL ;
    SHAPE ABUTMENT ;
    PORT
      LAYER M4 ;
      RECT 0 22.224 0.024 22.248 ;
    END
  END rw0_rd_out[198]
  PIN rw0_rd_out[199]
    DIRECTION OUTPUT ;
    USE SIGNAL ;
    SHAPE ABUTMENT ;
    PORT
      LAYER M4 ;
      RECT 0 22.272 0.024 22.296 ;
    END
  END rw0_rd_out[199]
  PIN rw0_rd_out[200]
    DIRECTION OUTPUT ;
    USE SIGNAL ;
    SHAPE ABUTMENT ;
    PORT
      LAYER M4 ;
      RECT 0 22.32 0.024 22.344 ;
    END
  END rw0_rd_out[200]
  PIN rw0_rd_out[201]
    DIRECTION OUTPUT ;
    USE SIGNAL ;
    SHAPE ABUTMENT ;
    PORT
      LAYER M4 ;
      RECT 0 22.368 0.024 22.392 ;
    END
  END rw0_rd_out[201]
  PIN rw0_rd_out[202]
    DIRECTION OUTPUT ;
    USE SIGNAL ;
    SHAPE ABUTMENT ;
    PORT
      LAYER M4 ;
      RECT 0 22.416 0.024 22.44 ;
    END
  END rw0_rd_out[202]
  PIN rw0_rd_out[203]
    DIRECTION OUTPUT ;
    USE SIGNAL ;
    SHAPE ABUTMENT ;
    PORT
      LAYER M4 ;
      RECT 0 22.464 0.024 22.488 ;
    END
  END rw0_rd_out[203]
  PIN rw0_rd_out[204]
    DIRECTION OUTPUT ;
    USE SIGNAL ;
    SHAPE ABUTMENT ;
    PORT
      LAYER M4 ;
      RECT 0 22.512 0.024 22.536 ;
    END
  END rw0_rd_out[204]
  PIN rw0_rd_out[205]
    DIRECTION OUTPUT ;
    USE SIGNAL ;
    SHAPE ABUTMENT ;
    PORT
      LAYER M4 ;
      RECT 0 22.56 0.024 22.584 ;
    END
  END rw0_rd_out[205]
  PIN rw0_rd_out[206]
    DIRECTION OUTPUT ;
    USE SIGNAL ;
    SHAPE ABUTMENT ;
    PORT
      LAYER M4 ;
      RECT 0 22.608 0.024 22.632 ;
    END
  END rw0_rd_out[206]
  PIN rw0_rd_out[207]
    DIRECTION OUTPUT ;
    USE SIGNAL ;
    SHAPE ABUTMENT ;
    PORT
      LAYER M4 ;
      RECT 0 22.656 0.024 22.68 ;
    END
  END rw0_rd_out[207]
  PIN rw0_rd_out[208]
    DIRECTION OUTPUT ;
    USE SIGNAL ;
    SHAPE ABUTMENT ;
    PORT
      LAYER M4 ;
      RECT 0 22.704 0.024 22.728 ;
    END
  END rw0_rd_out[208]
  PIN rw0_rd_out[209]
    DIRECTION OUTPUT ;
    USE SIGNAL ;
    SHAPE ABUTMENT ;
    PORT
      LAYER M4 ;
      RECT 0 22.752 0.024 22.776 ;
    END
  END rw0_rd_out[209]
  PIN rw0_rd_out[210]
    DIRECTION OUTPUT ;
    USE SIGNAL ;
    SHAPE ABUTMENT ;
    PORT
      LAYER M4 ;
      RECT 0 22.8 0.024 22.824 ;
    END
  END rw0_rd_out[210]
  PIN rw0_rd_out[211]
    DIRECTION OUTPUT ;
    USE SIGNAL ;
    SHAPE ABUTMENT ;
    PORT
      LAYER M4 ;
      RECT 0 22.848 0.024 22.872 ;
    END
  END rw0_rd_out[211]
  PIN rw0_rd_out[212]
    DIRECTION OUTPUT ;
    USE SIGNAL ;
    SHAPE ABUTMENT ;
    PORT
      LAYER M4 ;
      RECT 0 22.896 0.024 22.92 ;
    END
  END rw0_rd_out[212]
  PIN rw0_rd_out[213]
    DIRECTION OUTPUT ;
    USE SIGNAL ;
    SHAPE ABUTMENT ;
    PORT
      LAYER M4 ;
      RECT 0 22.944 0.024 22.968 ;
    END
  END rw0_rd_out[213]
  PIN rw0_rd_out[214]
    DIRECTION OUTPUT ;
    USE SIGNAL ;
    SHAPE ABUTMENT ;
    PORT
      LAYER M4 ;
      RECT 0 22.992 0.024 23.016 ;
    END
  END rw0_rd_out[214]
  PIN rw0_rd_out[215]
    DIRECTION OUTPUT ;
    USE SIGNAL ;
    SHAPE ABUTMENT ;
    PORT
      LAYER M4 ;
      RECT 0 23.04 0.024 23.064 ;
    END
  END rw0_rd_out[215]
  PIN rw0_rd_out[216]
    DIRECTION OUTPUT ;
    USE SIGNAL ;
    SHAPE ABUTMENT ;
    PORT
      LAYER M4 ;
      RECT 0 23.088 0.024 23.112 ;
    END
  END rw0_rd_out[216]
  PIN rw0_rd_out[217]
    DIRECTION OUTPUT ;
    USE SIGNAL ;
    SHAPE ABUTMENT ;
    PORT
      LAYER M4 ;
      RECT 0 23.136 0.024 23.16 ;
    END
  END rw0_rd_out[217]
  PIN rw0_rd_out[218]
    DIRECTION OUTPUT ;
    USE SIGNAL ;
    SHAPE ABUTMENT ;
    PORT
      LAYER M4 ;
      RECT 0 23.184 0.024 23.208 ;
    END
  END rw0_rd_out[218]
  PIN rw0_rd_out[219]
    DIRECTION OUTPUT ;
    USE SIGNAL ;
    SHAPE ABUTMENT ;
    PORT
      LAYER M4 ;
      RECT 0 23.232 0.024 23.256 ;
    END
  END rw0_rd_out[219]
  PIN rw0_rd_out[220]
    DIRECTION OUTPUT ;
    USE SIGNAL ;
    SHAPE ABUTMENT ;
    PORT
      LAYER M4 ;
      RECT 0 23.28 0.024 23.304 ;
    END
  END rw0_rd_out[220]
  PIN rw0_rd_out[221]
    DIRECTION OUTPUT ;
    USE SIGNAL ;
    SHAPE ABUTMENT ;
    PORT
      LAYER M4 ;
      RECT 0 23.328 0.024 23.352 ;
    END
  END rw0_rd_out[221]
  PIN rw0_rd_out[222]
    DIRECTION OUTPUT ;
    USE SIGNAL ;
    SHAPE ABUTMENT ;
    PORT
      LAYER M4 ;
      RECT 0 23.376 0.024 23.4 ;
    END
  END rw0_rd_out[222]
  PIN rw0_rd_out[223]
    DIRECTION OUTPUT ;
    USE SIGNAL ;
    SHAPE ABUTMENT ;
    PORT
      LAYER M4 ;
      RECT 0 23.424 0.024 23.448 ;
    END
  END rw0_rd_out[223]
  PIN rw0_rd_out[224]
    DIRECTION OUTPUT ;
    USE SIGNAL ;
    SHAPE ABUTMENT ;
    PORT
      LAYER M4 ;
      RECT 0 23.472 0.024 23.496 ;
    END
  END rw0_rd_out[224]
  PIN rw0_rd_out[225]
    DIRECTION OUTPUT ;
    USE SIGNAL ;
    SHAPE ABUTMENT ;
    PORT
      LAYER M4 ;
      RECT 0 23.52 0.024 23.544 ;
    END
  END rw0_rd_out[225]
  PIN rw0_rd_out[226]
    DIRECTION OUTPUT ;
    USE SIGNAL ;
    SHAPE ABUTMENT ;
    PORT
      LAYER M4 ;
      RECT 0 23.568 0.024 23.592 ;
    END
  END rw0_rd_out[226]
  PIN rw0_rd_out[227]
    DIRECTION OUTPUT ;
    USE SIGNAL ;
    SHAPE ABUTMENT ;
    PORT
      LAYER M4 ;
      RECT 0 23.616 0.024 23.64 ;
    END
  END rw0_rd_out[227]
  PIN rw0_rd_out[228]
    DIRECTION OUTPUT ;
    USE SIGNAL ;
    SHAPE ABUTMENT ;
    PORT
      LAYER M4 ;
      RECT 0 23.664 0.024 23.688 ;
    END
  END rw0_rd_out[228]
  PIN rw0_rd_out[229]
    DIRECTION OUTPUT ;
    USE SIGNAL ;
    SHAPE ABUTMENT ;
    PORT
      LAYER M4 ;
      RECT 0 23.712 0.024 23.736 ;
    END
  END rw0_rd_out[229]
  PIN rw0_rd_out[230]
    DIRECTION OUTPUT ;
    USE SIGNAL ;
    SHAPE ABUTMENT ;
    PORT
      LAYER M4 ;
      RECT 0 23.76 0.024 23.784 ;
    END
  END rw0_rd_out[230]
  PIN rw0_rd_out[231]
    DIRECTION OUTPUT ;
    USE SIGNAL ;
    SHAPE ABUTMENT ;
    PORT
      LAYER M4 ;
      RECT 0 23.808 0.024 23.832 ;
    END
  END rw0_rd_out[231]
  PIN rw0_rd_out[232]
    DIRECTION OUTPUT ;
    USE SIGNAL ;
    SHAPE ABUTMENT ;
    PORT
      LAYER M4 ;
      RECT 0 23.856 0.024 23.88 ;
    END
  END rw0_rd_out[232]
  PIN rw0_rd_out[233]
    DIRECTION OUTPUT ;
    USE SIGNAL ;
    SHAPE ABUTMENT ;
    PORT
      LAYER M4 ;
      RECT 0 23.904 0.024 23.928 ;
    END
  END rw0_rd_out[233]
  PIN rw0_rd_out[234]
    DIRECTION OUTPUT ;
    USE SIGNAL ;
    SHAPE ABUTMENT ;
    PORT
      LAYER M4 ;
      RECT 0 23.952 0.024 23.976 ;
    END
  END rw0_rd_out[234]
  PIN rw0_rd_out[235]
    DIRECTION OUTPUT ;
    USE SIGNAL ;
    SHAPE ABUTMENT ;
    PORT
      LAYER M4 ;
      RECT 0 24 0.024 24.024 ;
    END
  END rw0_rd_out[235]
  PIN rw0_rd_out[236]
    DIRECTION OUTPUT ;
    USE SIGNAL ;
    SHAPE ABUTMENT ;
    PORT
      LAYER M4 ;
      RECT 0 24.048 0.024 24.072 ;
    END
  END rw0_rd_out[236]
  PIN rw0_rd_out[237]
    DIRECTION OUTPUT ;
    USE SIGNAL ;
    SHAPE ABUTMENT ;
    PORT
      LAYER M4 ;
      RECT 0 24.096 0.024 24.12 ;
    END
  END rw0_rd_out[237]
  PIN rw0_rd_out[238]
    DIRECTION OUTPUT ;
    USE SIGNAL ;
    SHAPE ABUTMENT ;
    PORT
      LAYER M4 ;
      RECT 0 24.144 0.024 24.168 ;
    END
  END rw0_rd_out[238]
  PIN rw0_rd_out[239]
    DIRECTION OUTPUT ;
    USE SIGNAL ;
    SHAPE ABUTMENT ;
    PORT
      LAYER M4 ;
      RECT 0 24.192 0.024 24.216 ;
    END
  END rw0_rd_out[239]
  PIN rw0_rd_out[240]
    DIRECTION OUTPUT ;
    USE SIGNAL ;
    SHAPE ABUTMENT ;
    PORT
      LAYER M4 ;
      RECT 0 24.24 0.024 24.264 ;
    END
  END rw0_rd_out[240]
  PIN rw0_rd_out[241]
    DIRECTION OUTPUT ;
    USE SIGNAL ;
    SHAPE ABUTMENT ;
    PORT
      LAYER M4 ;
      RECT 0 24.288 0.024 24.312 ;
    END
  END rw0_rd_out[241]
  PIN rw0_rd_out[242]
    DIRECTION OUTPUT ;
    USE SIGNAL ;
    SHAPE ABUTMENT ;
    PORT
      LAYER M4 ;
      RECT 0 24.336 0.024 24.36 ;
    END
  END rw0_rd_out[242]
  PIN rw0_rd_out[243]
    DIRECTION OUTPUT ;
    USE SIGNAL ;
    SHAPE ABUTMENT ;
    PORT
      LAYER M4 ;
      RECT 0 24.384 0.024 24.408 ;
    END
  END rw0_rd_out[243]
  PIN rw0_rd_out[244]
    DIRECTION OUTPUT ;
    USE SIGNAL ;
    SHAPE ABUTMENT ;
    PORT
      LAYER M4 ;
      RECT 0 24.432 0.024 24.456 ;
    END
  END rw0_rd_out[244]
  PIN rw0_rd_out[245]
    DIRECTION OUTPUT ;
    USE SIGNAL ;
    SHAPE ABUTMENT ;
    PORT
      LAYER M4 ;
      RECT 0 24.48 0.024 24.504 ;
    END
  END rw0_rd_out[245]
  PIN rw0_rd_out[246]
    DIRECTION OUTPUT ;
    USE SIGNAL ;
    SHAPE ABUTMENT ;
    PORT
      LAYER M4 ;
      RECT 0 24.528 0.024 24.552 ;
    END
  END rw0_rd_out[246]
  PIN rw0_rd_out[247]
    DIRECTION OUTPUT ;
    USE SIGNAL ;
    SHAPE ABUTMENT ;
    PORT
      LAYER M4 ;
      RECT 0 24.576 0.024 24.6 ;
    END
  END rw0_rd_out[247]
  PIN rw0_rd_out[248]
    DIRECTION OUTPUT ;
    USE SIGNAL ;
    SHAPE ABUTMENT ;
    PORT
      LAYER M4 ;
      RECT 0 24.624 0.024 24.648 ;
    END
  END rw0_rd_out[248]
  PIN rw0_rd_out[249]
    DIRECTION OUTPUT ;
    USE SIGNAL ;
    SHAPE ABUTMENT ;
    PORT
      LAYER M4 ;
      RECT 0 24.672 0.024 24.696 ;
    END
  END rw0_rd_out[249]
  PIN rw0_rd_out[250]
    DIRECTION OUTPUT ;
    USE SIGNAL ;
    SHAPE ABUTMENT ;
    PORT
      LAYER M4 ;
      RECT 0 24.72 0.024 24.744 ;
    END
  END rw0_rd_out[250]
  PIN rw0_rd_out[251]
    DIRECTION OUTPUT ;
    USE SIGNAL ;
    SHAPE ABUTMENT ;
    PORT
      LAYER M4 ;
      RECT 0 24.768 0.024 24.792 ;
    END
  END rw0_rd_out[251]
  PIN rw0_rd_out[252]
    DIRECTION OUTPUT ;
    USE SIGNAL ;
    SHAPE ABUTMENT ;
    PORT
      LAYER M4 ;
      RECT 0 24.816 0.024 24.84 ;
    END
  END rw0_rd_out[252]
  PIN rw0_rd_out[253]
    DIRECTION OUTPUT ;
    USE SIGNAL ;
    SHAPE ABUTMENT ;
    PORT
      LAYER M4 ;
      RECT 0 24.864 0.024 24.888 ;
    END
  END rw0_rd_out[253]
  PIN rw0_rd_out[254]
    DIRECTION OUTPUT ;
    USE SIGNAL ;
    SHAPE ABUTMENT ;
    PORT
      LAYER M4 ;
      RECT 0 24.912 0.024 24.936 ;
    END
  END rw0_rd_out[254]
  PIN rw0_rd_out[255]
    DIRECTION OUTPUT ;
    USE SIGNAL ;
    SHAPE ABUTMENT ;
    PORT
      LAYER M4 ;
      RECT 0 24.96 0.024 24.984 ;
    END
  END rw0_rd_out[255]
  PIN rw0_addr_in[0]
    DIRECTION INPUT ;
    USE SIGNAL ;
    SHAPE ABUTMENT ;
    PORT
      LAYER M4 ;
      RECT 0 25.008 0.024 25.032 ;
    END
  END rw0_addr_in[0]
  PIN rw0_addr_in[1]
    DIRECTION INPUT ;
    USE SIGNAL ;
    SHAPE ABUTMENT ;
    PORT
      LAYER M4 ;
      RECT 0 25.056 0.024 25.08 ;
    END
  END rw0_addr_in[1]
  PIN rw0_addr_in[2]
    DIRECTION INPUT ;
    USE SIGNAL ;
    SHAPE ABUTMENT ;
    PORT
      LAYER M4 ;
      RECT 0 25.104 0.024 25.128 ;
    END
  END rw0_addr_in[2]
  PIN rw0_addr_in[3]
    DIRECTION INPUT ;
    USE SIGNAL ;
    SHAPE ABUTMENT ;
    PORT
      LAYER M4 ;
      RECT 0 25.152 0.024 25.176 ;
    END
  END rw0_addr_in[3]
  PIN rw0_addr_in[4]
    DIRECTION INPUT ;
    USE SIGNAL ;
    SHAPE ABUTMENT ;
    PORT
      LAYER M4 ;
      RECT 0 25.2 0.024 25.224 ;
    END
  END rw0_addr_in[4]
  PIN rw0_addr_in[5]
    DIRECTION INPUT ;
    USE SIGNAL ;
    SHAPE ABUTMENT ;
    PORT
      LAYER M4 ;
      RECT 0 25.248 0.024 25.272 ;
    END
  END rw0_addr_in[5]
  PIN rw0_addr_in[6]
    DIRECTION INPUT ;
    USE SIGNAL ;
    SHAPE ABUTMENT ;
    PORT
      LAYER M4 ;
      RECT 0 25.296 0.024 25.32 ;
    END
  END rw0_addr_in[6]
  PIN rw0_addr_in[7]
    DIRECTION INPUT ;
    USE SIGNAL ;
    SHAPE ABUTMENT ;
    PORT
      LAYER M4 ;
      RECT 0 25.344 0.024 25.368 ;
    END
  END rw0_addr_in[7]
  PIN rw0_we_in
    DIRECTION INPUT ;
    USE SIGNAL ;
    SHAPE ABUTMENT ;
    PORT
      LAYER M4 ;
      RECT 0 25.392 0.024 25.416 ;
    END
  END rw0_we_in
  PIN rw0_ce_in
    DIRECTION INPUT ;
    USE SIGNAL ;
    SHAPE ABUTMENT ;
    PORT
      LAYER M4 ;
      RECT 0 25.44 0.024 25.464 ;
    END
  END rw0_ce_in
  PIN rw0_clk
    DIRECTION INPUT ;
    USE SIGNAL ;
    SHAPE ABUTMENT ;
    PORT
      LAYER M4 ;
      RECT 0 25.488 0.024 25.512 ;
    END
  END rw0_clk
  PIN VSS
    DIRECTION INOUT ;
    USE GROUND ;
    PORT
      LAYER M4 ;
      RECT 0.048 0 69.294 0.096 ;
      RECT 0.048 0.768 69.294 0.864 ;
      RECT 0.048 1.536 69.294 1.632 ;
      RECT 0.048 2.304 69.294 2.4 ;
      RECT 0.048 3.072 69.294 3.168 ;
      RECT 0.048 3.84 69.294 3.936 ;
      RECT 0.048 4.608 69.294 4.704 ;
      RECT 0.048 5.376 69.294 5.472 ;
      RECT 0.048 6.144 69.294 6.24 ;
      RECT 0.048 6.912 69.294 7.008 ;
      RECT 0.048 7.68 69.294 7.776 ;
      RECT 0.048 8.448 69.294 8.544 ;
      RECT 0.048 9.216 69.294 9.312 ;
      RECT 0.048 9.984 69.294 10.08 ;
      RECT 0.048 10.752 69.294 10.848 ;
      RECT 0.048 11.52 69.294 11.616 ;
      RECT 0.048 12.288 69.294 12.384 ;
      RECT 0.048 13.056 69.294 13.152 ;
      RECT 0.048 13.824 69.294 13.92 ;
      RECT 0.048 14.592 69.294 14.688 ;
      RECT 0.048 15.36 69.294 15.456 ;
      RECT 0.048 16.128 69.294 16.224 ;
      RECT 0.048 16.896 69.294 16.992 ;
      RECT 0.048 17.664 69.294 17.76 ;
      RECT 0.048 18.432 69.294 18.528 ;
      RECT 0.048 19.2 69.294 19.296 ;
      RECT 0.048 19.968 69.294 20.064 ;
      RECT 0.048 20.736 69.294 20.832 ;
      RECT 0.048 21.504 69.294 21.6 ;
      RECT 0.048 22.272 69.294 22.368 ;
      RECT 0.048 23.04 69.294 23.136 ;
      RECT 0.048 23.808 69.294 23.904 ;
      RECT 0.048 24.576 69.294 24.672 ;
      RECT 0.048 25.344 69.294 25.44 ;
      RECT 0.048 26.112 69.294 26.208 ;
      RECT 0.048 26.88 69.294 26.976 ;
      RECT 0.048 27.648 69.294 27.744 ;
      RECT 0.048 28.416 69.294 28.512 ;
      RECT 0.048 29.184 69.294 29.28 ;
      RECT 0.048 29.952 69.294 30.048 ;
      RECT 0.048 30.72 69.294 30.816 ;
      RECT 0.048 31.488 69.294 31.584 ;
      RECT 0.048 32.256 69.294 32.352 ;
    END
  END VSS
  PIN VDD
    DIRECTION INOUT ;
    USE POWER ;
    PORT
      LAYER M4 ;
      RECT 0.048 0.384 69.294 0.48 ;
      RECT 0.048 1.152 69.294 1.248 ;
      RECT 0.048 1.92 69.294 2.016 ;
      RECT 0.048 2.688 69.294 2.784 ;
      RECT 0.048 3.456 69.294 3.552 ;
      RECT 0.048 4.224 69.294 4.32 ;
      RECT 0.048 4.992 69.294 5.088 ;
      RECT 0.048 5.76 69.294 5.856 ;
      RECT 0.048 6.528 69.294 6.624 ;
      RECT 0.048 7.296 69.294 7.392 ;
      RECT 0.048 8.064 69.294 8.16 ;
      RECT 0.048 8.832 69.294 8.928 ;
      RECT 0.048 9.6 69.294 9.696 ;
      RECT 0.048 10.368 69.294 10.464 ;
      RECT 0.048 11.136 69.294 11.232 ;
      RECT 0.048 11.904 69.294 12 ;
      RECT 0.048 12.672 69.294 12.768 ;
      RECT 0.048 13.44 69.294 13.536 ;
      RECT 0.048 14.208 69.294 14.304 ;
      RECT 0.048 14.976 69.294 15.072 ;
      RECT 0.048 15.744 69.294 15.84 ;
      RECT 0.048 16.512 69.294 16.608 ;
      RECT 0.048 17.28 69.294 17.376 ;
      RECT 0.048 18.048 69.294 18.144 ;
      RECT 0.048 18.816 69.294 18.912 ;
      RECT 0.048 19.584 69.294 19.68 ;
      RECT 0.048 20.352 69.294 20.448 ;
      RECT 0.048 21.12 69.294 21.216 ;
      RECT 0.048 21.888 69.294 21.984 ;
      RECT 0.048 22.656 69.294 22.752 ;
      RECT 0.048 23.424 69.294 23.52 ;
      RECT 0.048 24.192 69.294 24.288 ;
      RECT 0.048 24.96 69.294 25.056 ;
      RECT 0.048 25.728 69.294 25.824 ;
      RECT 0.048 26.496 69.294 26.592 ;
      RECT 0.048 27.264 69.294 27.36 ;
      RECT 0.048 28.032 69.294 28.128 ;
      RECT 0.048 28.8 69.294 28.896 ;
      RECT 0.048 29.568 69.294 29.664 ;
      RECT 0.048 30.336 69.294 30.432 ;
      RECT 0.048 31.104 69.294 31.2 ;
      RECT 0.048 31.872 69.294 31.968 ;
    END
  END VDD
  OBS
    LAYER M1 ;
    RECT 0 0 69.342 32.504 ;
    LAYER M2 ;
    RECT 0 0 69.342 32.504 ;
    LAYER M3 ;
    RECT 0 0 69.342 32.504 ;
  END
END ht_asap7_rocketgemmini_rockettile_icache_data_arrays_0_ext

END LIBRARY
